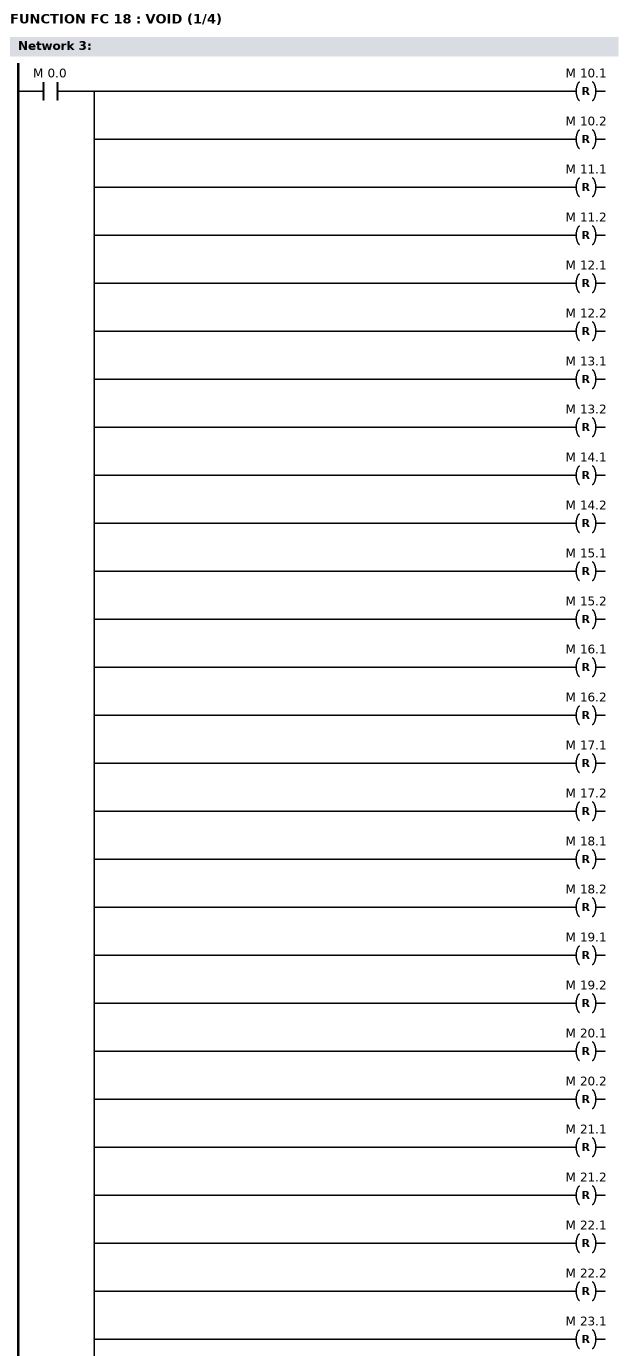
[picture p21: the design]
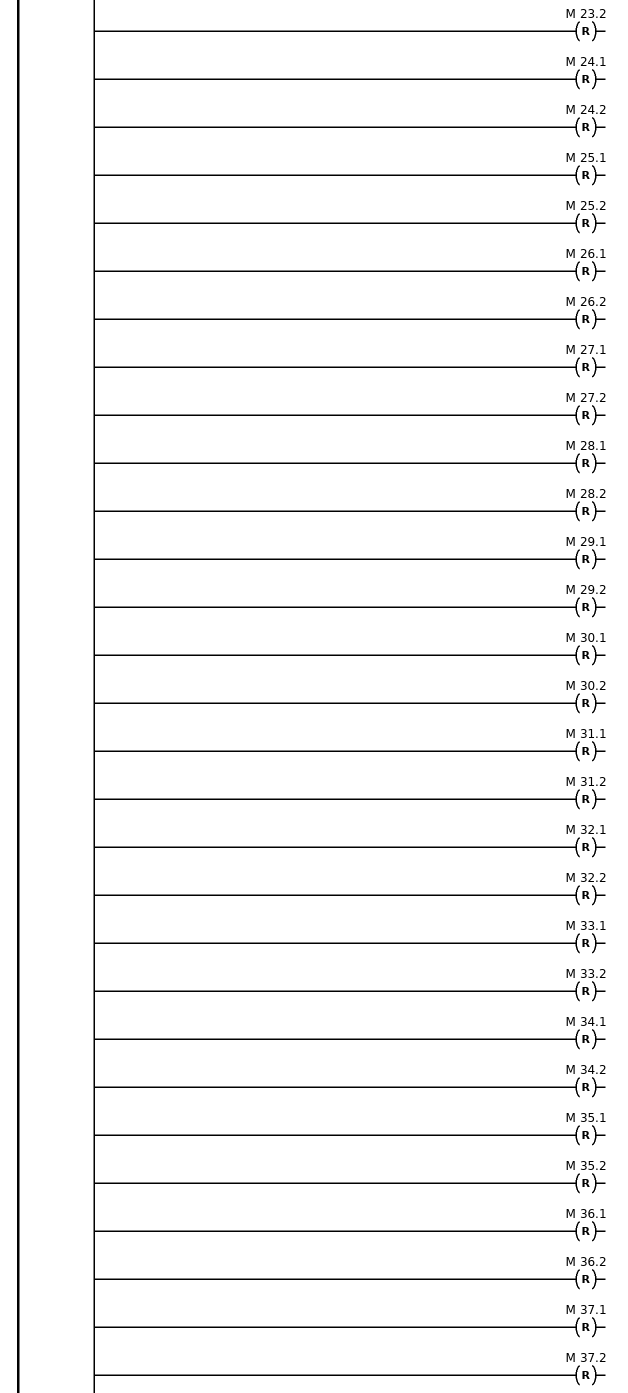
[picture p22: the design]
FUNCTION FC 33 : VOID
  NAME: INITREG  // INIT REG
  BEGIN
  NETWORK
       //;
       L   2#0000000000000001;
       T   MB 160;
       T   MB 161;
       T   MW 164;
       L   2#0000000000000000;
       T   MW 162;
       //;
       //;
       OPN DB 200;
  //      CALL OB 250;
  // *** Error in Line    5060  (FB 200):  Block does not exist. ***
       OPN DB 201;
  //      CALL OB 250;
  // *** Error in Line    5063  (FB 200):  Block does not exist. ***
       OPN DB 202;
  //      CALL OB 250;
  // *** Error in Line    5066  (FB 200):  Block does not exist. ***
       OPN DB 203;
  //      CALL OB 250;
  // *** Error in Line    5069  (FB 200):  Block does not exist. ***
       OPN DB 204;
  //      CALL OB 250;
  // *** Error in Line    5072  (FB 200):  Block does not exist. ***
       OPN DB 205;
  //      CALL OB 250;
  // *** Error in Line    5075  (FB 200):  Block does not exist. ***
       OPN DB 206;
  //      CALL OB 250;
  // *** Error in Line    5078  (FB 200):  Block does not exist. ***
       OPN DB 207;
  //      CALL OB 250;
  // *** Error in Line    5081  (FB 200):  Block does not exist. ***
       OPN DB 208;
  //      CALL OB 250;
  // *** Error in Line    5084  (FB 200):  Block does not exist. ***
       OPN DB 209;
  //      CALL OB 250;
  // *** Error in Line    5087  (FB 200):  Block does not exist. ***
       OPN DB 210;
  //      CALL OB 250;
  // *** Error in Line    5090  (FB 200):  Block does not exist. ***
       OPN DB 211;
  //      CALL OB 250;
  // *** Error in Line    5093  (FB 200):  Block does not exist. ***
       OPN DB 212;
  //      CALL OB 250;
  // *** Error in Line    5096  (FB 200):  Block does not exist. ***
       OPN DB 213;
  //      CALL OB 250;
  // *** Error in Line    5099  (FB 200):  Block does not exist. ***
       OPN DB 214;
  //      CALL OB 250;
  // *** Error in Line    5102  (FB 200):  Block does not exist. ***
       OPN DB 215;
  //      CALL OB 250;
  // *** Error in Line    5105  (FB 200):  Block does not exist. ***
       OPN DB 216;
  //      CALL OB 250;
  // *** Error in Line    5108  (FB 200):  Block does not exist. ***
       OPN DB 217;
  //      CALL OB 250;
  // *** Error in Line    5111  (FB 200):  Block does not exist. ***
       OPN DB 218;
  //      CALL OB 250;
  // *** Error in Line    5114  (FB 200):  Block does not exist. ***
       OPN DB 219;
  //      CALL OB 250;
  // *** Error in Line    5117  (FB 200):  Block does not exist. ***
       OPN DB 220;
  //      CALL OB 250;
  // *** Error in Line    5120  (FB 200):  Block does not exist. ***
       OPN DB 221;
  //      CALL OB 250;
  // *** Error in Line    5123  (FB 200):  Block does not exist. ***
       OPN DB 222;
  //      CALL OB 250;
  // *** Error in Line    5126  (FB 200):  Block does not exist. ***
       OPN DB 223;
  //      CALL OB 250;
  // *** Error in Line    5129  (FB 200):  Block does not exist. ***
       OPN DB 224;
  //      CALL OB 250;
  // *** Error in Line    5132  (FB 200):  Block does not exist. ***
       OPN DB 225;
  //      CALL OB 250;
  // *** Error in Line    5135  (FB 200):  Block does not exist. ***
       OPN DB 226;
  //      CALL OB 250;
  // *** Error in Line    5138  (FB 200):  Block does not exist. ***
       OPN DB 227;
  //      CALL OB 250;
  // *** Error in Line    5141  (FB 200):  Block does not exist. ***
       //;
END_FUNCTION

FUNCTION FC 15 : VOID
  NAME: MOTOR
  BEGIN
  NETWORK
  TITLE = MOTOR 05
  NETWORK
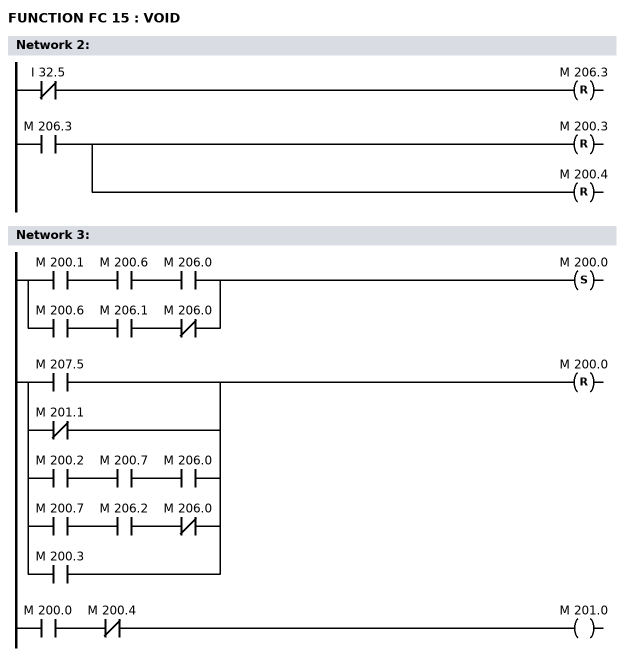
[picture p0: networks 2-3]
       AN  I 32.5;
       R   M 206.3;
       //;
       A   M 206.3;
       R   M 200.3;
       R   M 200.4;
  NETWORK
       A   M 200.1;
       A   M 200.6;
       A   M 206.0;
       O;
       A   M 200.6;
       A   M 206.1;
       AN  M 206.0;
       S   M 200.0;
       O   M 207.5;
       ON  M 201.1;
       O;
       A   M 200.2;
       A   M 200.7;
       A   M 206.0;
       O;
       A   M 200.7;
       A   M 206.2;
       AN  M 206.0;
       O   M 200.3;
       R   M 200.0;
       A   M 200.0;
       AN  M 200.4;
       =   M 201.0;
  NETWORK
  NETWORK
       AN  M 201.0;
       A   M 201.2;
       O;
       A   M 201.0;
       AN  M 201.2;
       =   M 209.0;
       AN  M 206.7;
       AN  M 209.0;
       =   M 209.1;
       AN  M 209.0;
       =   M 206.7;
       A   M 209.1;
       JC  M001;
       A   M 209.0;
       A   M 4.2;
       JC  M002;
       JU  M003;
  M001:L   15;
       T   MW 204;
       JU  M003;
  M002:L   MW 204;
       L   0;
       ==I;
       JC  M003;
       L   MW 204;
       +   -1;
       T   MW 204;
  M003:  NOP 0;
    NETWORK
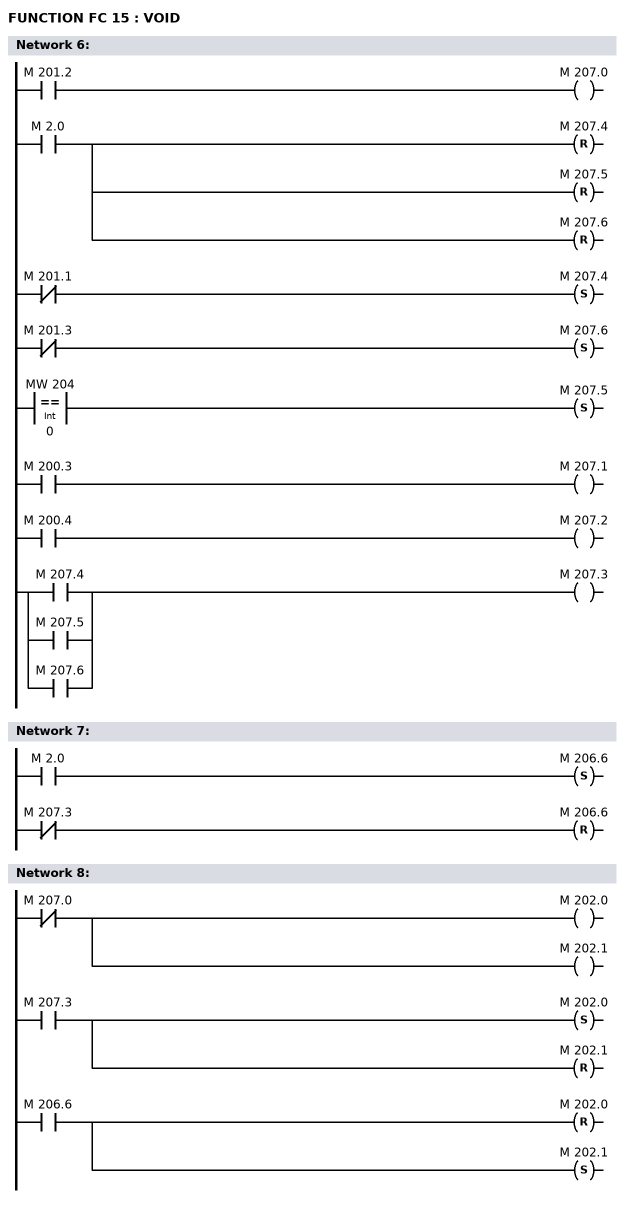
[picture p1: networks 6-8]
       A   M 201.2;
       =   M 207.0;
       A   M 2.0;
       R   M 207.4;
       R   M 207.5;
       R   M 207.6;
       AN  M 201.1;
       S   M 207.4;
       AN  M 201.3;
       S   M 207.6;
       L   MW 204;
       L   0;
       ==I;
       S   M 207.5;
       A   M 200.3;
       =   M 207.1;
       A   M 200.4;
       =   M 207.2;
       A   M 207.4;
       O   M 207.5;
       O   M 207.6;
       =   M 207.3;
  NETWORK
       A   M 2.0;
       S   M 206.6;
       AN  M 207.3;
       R   M 206.6;
  NETWORK
       AN  M 207.0;
       =   M 202.0;
       =   M 202.1;
       //;
       A   M 207.3;
       S   M 202.0;
       R   M 202.1;
       //;
       A   M 206.6;
       R   M 202.0;
       S   M 202.1;
       //;
  NETWORK
END_FUNCTION

FUNCTION FC 16 : VOID
  NAME: KLEP20  // KLEP 20
  BEGIN
  NETWORK
  NETWORK
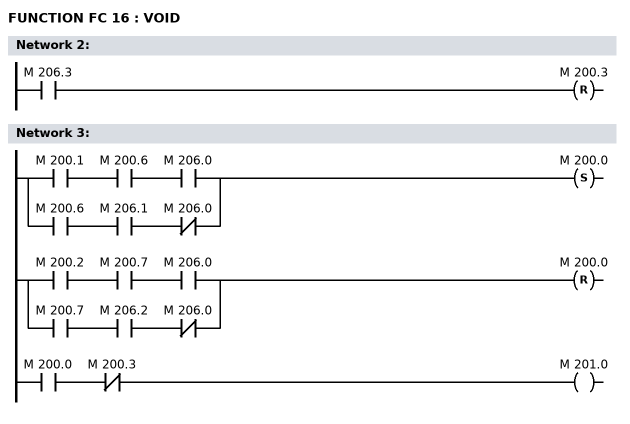
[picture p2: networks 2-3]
       A   M 206.3;
       R   M 200.3;
  NETWORK
       A   M 200.1;
       A   M 200.6;
       A   M 206.0;
       O;
       A   M 200.6;
       A   M 206.1;
       AN  M 206.0;
       S   M 200.0;
       A   M 200.2;
       A   M 200.7;
       A   M 206.0;
       O;
       A   M 200.7;
       A   M 206.2;
       AN  M 206.0;
       R   M 200.0;
       A   M 200.0;
       AN  M 200.3;
       =   M 201.0;
  NETWORK
  NETWORK
       AN  M 201.0;
       AN  M 201.2;
       O;
       A   M 201.0;
       AN  M 201.1;
       =   M 209.0;
       A   M 206.7;
       AN  M 209.0;
       =   M 209.1;
       A   M 209.0;
       =   M 206.7;
       A   M 209.1;
       JC  M001;
       A   M 209.0;
       A   M 4.2;
       JC  M002;
       JU  M003;
  M001:L   60;
       T   MW 204;
       JU  M003;
  M002:L   MW 204;
       L   0;
       ==I;
       JC  M003;
       L   MW 204;
       +   -1;
       T   MW 204;
  M003:  NOP 0;
    NETWORK
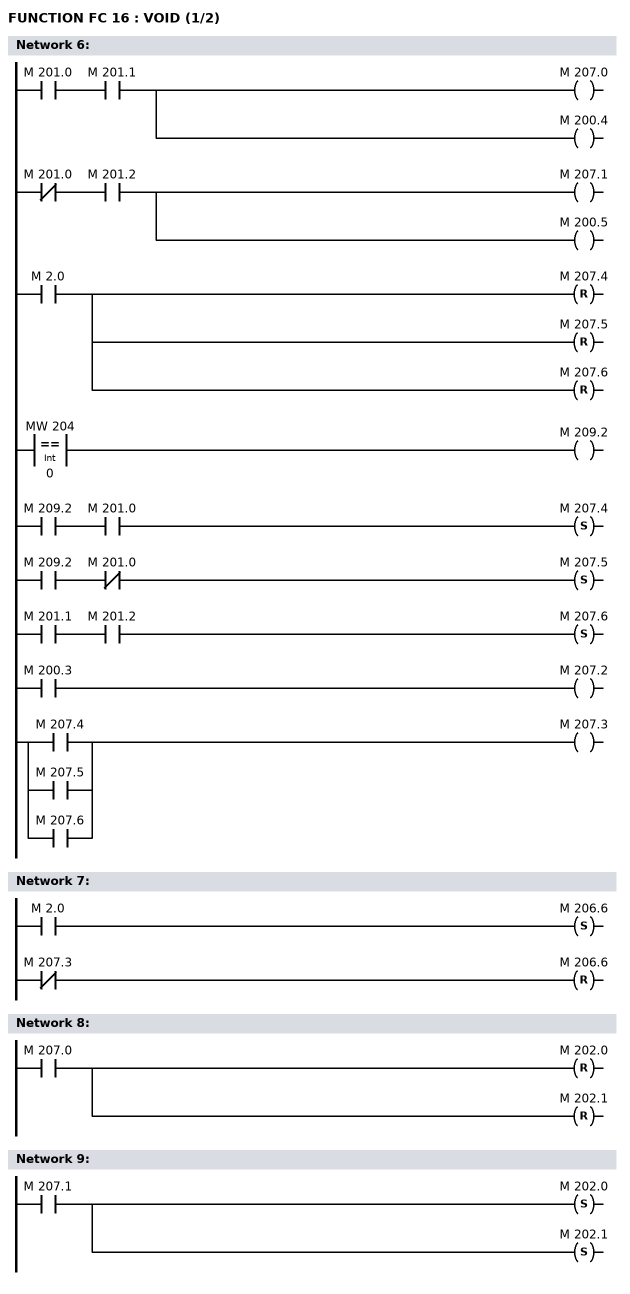
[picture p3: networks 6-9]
       A   M 201.0;
       A   M 201.1;
       =   M 207.0;
       =   M 200.4;
       AN  M 201.0;
       A   M 201.2;
       =   M 207.1;
       =   M 200.5;
       A   M 2.0;
       R   M 207.4;
       R   M 207.5;
       R   M 207.6;
       L   MW 204;
       L   0;
       ==I;
       =   M 209.2;
       A   M 209.2;
       A   M 201.0;
       S   M 207.4;
       A   M 209.2;
       AN  M 201.0;
       S   M 207.5;
       A   M 201.1;
       A   M 201.2;
       S   M 207.6;
       A   M 200.3;
       =   M 207.2;
       A   M 207.4;
       O   M 207.5;
       O   M 207.6;
       =   M 207.3;
  NETWORK
       A   M 2.0;
       S   M 206.6;
       AN  M 207.3;
       R   M 206.6;
  NETWORK
       A   M 207.0;
       R   M 202.0;
       R   M 202.1;
  NETWORK
       A   M 207.1;
       S   M 202.0;
       S   M 202.1;
  NETWORK
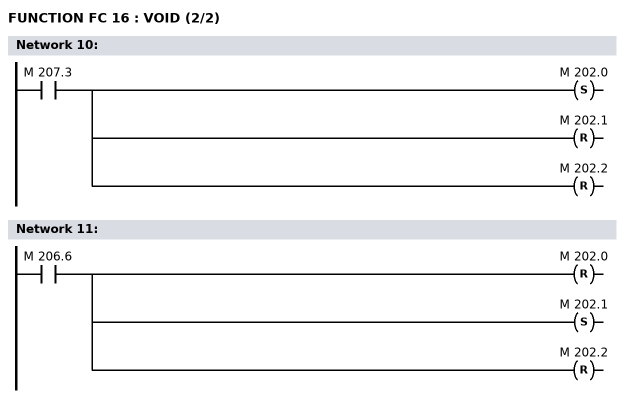
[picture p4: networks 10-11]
       A   M 207.3;
       S   M 202.0;
       R   M 202.1;
       R   M 202.2;
  NETWORK
       A   M 206.6;
       R   M 202.0;
       S   M 202.1;
       R   M 202.2;
  NETWORK


END_FUNCTION

FUNCTION FC 17 : VOID
  NAME: NVKLP20  // NVKLP 20
  BEGIN
  NETWORK
  NETWORK
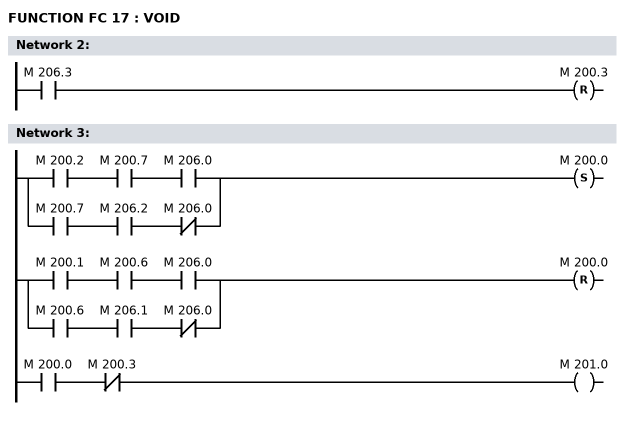
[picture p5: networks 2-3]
       A   M 206.3;
       R   M 200.3;
  NETWORK
       A   M 200.2;
       A   M 200.7;
       A   M 206.0;
       O;
       A   M 200.7;
       A   M 206.2;
       AN  M 206.0;
       S   M 200.0;
       A   M 200.1;
       A   M 200.6;
       A   M 206.0;
       O;
       A   M 200.6;
       A   M 206.1;
       AN  M 206.0;
       R   M 200.0;
       A   M 200.0;
       AN  M 200.3;
       =   M 201.0;
  NETWORK
  NETWORK
       A   M 201.0;
       AN  M 201.2;
       O;
       AN  M 201.0;
       AN  M 201.1;
       =   M 209.0;
       A   M 206.7;
       AN  M 209.0;
       =   M 209.1;
       A   M 209.0;
       =   M 206.7;
       A   M 209.1;
       JC  M001;
       A   M 209.0;
       A   M 4.2;
       JC  M002;
       JU  M003;
  M001:L   20;
       T   MW 204;
       JU  M003;
  M002:L   MW 204;
       L   0;
       ==I;
       JC  M003;
       L   MW 204;
       +   -1;
       T   MW 204;
  M003:  NOP 0;
    NETWORK
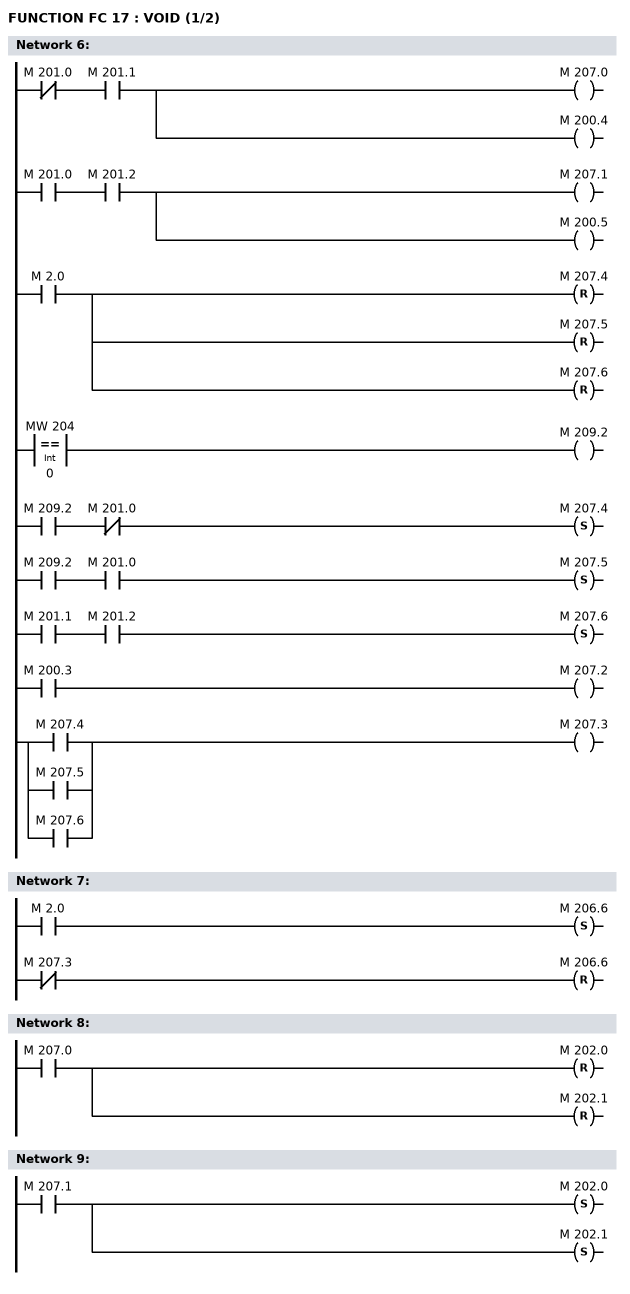
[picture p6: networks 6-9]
       AN  M 201.0;
       A   M 201.1;
       =   M 207.0;
       =   M 200.4;
       A   M 201.0;
       A   M 201.2;
       =   M 207.1;
       =   M 200.5;
       A   M 2.0;
       R   M 207.4;
       R   M 207.5;
       R   M 207.6;
       L   MW 204;
       L   0;
       ==I;
       =   M 209.2;
       A   M 209.2;
       AN  M 201.0;
       S   M 207.4;
       A   M 209.2;
       A   M 201.0;
       S   M 207.5;
       A   M 201.1;
       A   M 201.2;
       S   M 207.6;
       A   M 200.3;
       =   M 207.2;
       A   M 207.4;
       O   M 207.5;
       O   M 207.6;
       =   M 207.3;
  NETWORK
       A   M 2.0;
       S   M 206.6;
       AN  M 207.3;
       R   M 206.6;
  NETWORK
       A   M 207.0;
       R   M 202.0;
       R   M 202.1;
  NETWORK
       A   M 207.1;
       S   M 202.0;
       S   M 202.1;
  NETWORK
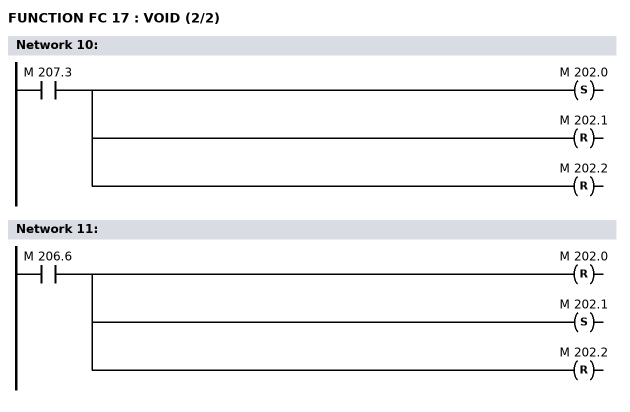
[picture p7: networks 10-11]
       A   M 207.3;
       S   M 202.0;
       R   M 202.1;
       R   M 202.2;
  NETWORK
       A   M 206.6;
       R   M 202.0;
       S   M 202.1;
       R   M 202.2;
  NETWORK


END_FUNCTION

FUNCTION FC 8 : VOID
  AUTHOR: _6107
  NAME: MK818STP
  BEGIN
  NETWORK
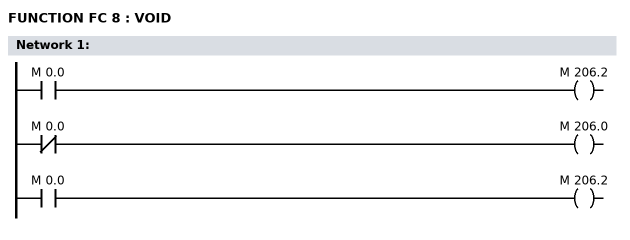
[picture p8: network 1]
       A   M 0.0;
       =   M 206.2;
       AN  M 0.0;
       =   M 206.0;
       A   M 0.0;
       =   M 206.2;


END_FUNCTION

FUNCTION FC 31 : VOID
  NAME: ANA_INKG  // ANA-INKG
  VAR_INPUT
    ANA       :word;      // ANA
    OPTI      :word;      // OPTI
    _DB       :block_db;  // DB
    VAN       :real;      // VAN
    TOT       :real;      // TOT
  END_VAR
  VAR_OUTPUT
    UITG      :dword;     // UITG
    UITF      :word;      // UITF
  END_VAR
  BEGIN
  NETWORK
       L   #ANA;
       L   8;
       /I;
       T   MW 200;
       //;
       L   #OPTI;
       T   MW 210;
       //;
       AN  M 211.0;
       JC  M001;
       L   MW 200;
       L   512;
       -I;
       T   MW 200;
       JU  M002;
       //;
  M001:AN  M 211.1;
       JC  M002;
       L   MW 200;
       L   39;
       +I;
       T   MW 200;
       //;
  M002:L   MW 200;
  //      CALL OB 220;
  // *** Error in Line    4796  (FB 150):  Block does not exist. ***
       DTR;
       T   MD 200;
       L   #TOT;
       L   #VAN;
       -R;
       L   +0.2048000E+04;
       /R;
       L   MD 200;
       *R;
       L   #VAN;
       +R;
       OPN #_DB ;
       T   #UITG;
       DTR;
       T   #UITF;


END_FUNCTION

FUNCTION FC 35 : VOID
  NAME: SCALE_UI  // SCALE-UI
  VAR_INPUT
    IN        :dword;     // IN
    VAN       :real;      // VAN
    TOT       :real;      // TOT
    DBIN      :block_db;  // DBIN
  END_VAR
  VAR_OUTPUT
    UIT       :word;      // UIT
  END_VAR
  BEGIN
  NETWORK
       OPN #DBIN ;
       L   #TOT;
       L   #VAN;
       -R;
       T   MD 200;
       L   #IN;
       L   #VAN;
       -R;
       L   MD 200;
       /R;
       L   +0.1024000E+04;
       *R;
       RND;
       T   MW 200;
       L   1024;
       >I;
       JC  M001;
       L   MW 200;
       L   -1024;
       <I;
       JC  M001;
       L   MW 200;
  M001:SLW 4;
       T   #UIT;


END_FUNCTION

FUNCTION FC 26 : VOID
  NAME: SEQ16
  BEGIN
  NETWORK
       //;
       //;
       //;
       AN  M 217.1;
       JC  M001;
       //;
       L   W#16#0;
       T   MW 210;
       L   W#16#1;
       T   MW 214;
       //;
       A   M 217.1;
       JC  M002;
       //;
  M001:A   M 211.1;
       AN  M 217.3;
       =   M 211.1;
       //;
       L   MW 210;
       L   W#16#0;
       OW;
       JZ  M003;
       //;
       L   W#16#FFFF;
       L   MW 212;
       XOW;
       L   MW 210;
       AW;
       JZ  M003;
       //;
       T   MW 214;
       T   MW 218;
       //;
       //;
  M002:A   M 0.1;
       =   M 217.1;
  M003:A   M 0.1;
       =   M 217.2;


END_FUNCTION

FUNCTION FC 27 : VOID
  NAME: SEQ32
  BEGIN
  NETWORK
       //;
       //;
       //;
       AN  M 101.2;
       JC  M001;
       //;
       L   W#16#0;
       SLW 15;
       T   MD 210;
       L   W#16#1;
       T   MD 218;
       //;
       A   M 101.2;
       JC  M002;
       //;
       //;
  M001:L   MW 210;
       L   W#16#0;
       OW;
       JP  M003;
       //;
       L   MW 212;
       L   W#16#0;
       OW;
       JZ  M004;
       //;
       //;
  M003:L   MD 210;
       T   MD 218;
       T   MD 226;
       L   W#16#0;
       SLW 15;
       T   MD 210;
       //;
  M002:A   M 0.1;
       =   M 101.2;
       //;
  M004:NOP 0;

END_FUNCTION

FUNCTION FC 28 : VOID
  NAME: ACTSTP
  BEGIN
  NETWORK
       //;
       //;
       A   M 0.1;
       =   M 223.0;
       //;
       L   MW 218;
       L   W#16#0;
       OW;
       JP  M001;
       //;
       L   MW 220;
       SSI 1;
       L   W#16#0;
       OW;
       JZ  M002;
       //;
  M001:A   M 0.0;
       =   M 223.0;
       //;
  M002:NOP 0;

END_FUNCTION

FUNCTION FC 29 : VOID
  NAME: GENTR
  BEGIN
  NETWORK
       L   MD 218;
       T   MD 230;
       //;
       L   W#16#1FF;
       L   MW 214;
       XOW;
       JP  M001;
       L   W#16#FFFE;
       L   MW 216;
       XOW;
       JZ  M002;
       //;
       //;
  M001:L   MD 230;
       //;
       A   M 233.0;
       A   M 109.2;
       JC  M003;
       //;
       A   M 233.0;
       JC  M004;
       //;
       A   M 230.0;
       JC  M004;
       //;
       A   M 109.2;
       A   M 231.7;
       JC  M003;
       //;
       SLD 1;
       AN  M 109.2;
       JC  M005;
       SLD 1;
       //;
       //;
  M005:T   MD 230;
       L   MW 216;
       AW;
       JP  M006;
       L   MW 230;
       L   MW 214;
       AW;
       JZ  M007;
       //;
  M006:L   MD 230;
       JU  M001;
       //;
       //;
  M003:L   W#16#0;
       T   MW 230;
       L   W#16#4;
       T   MW 232;
       JU  M005;
       //;
  M004:L   W#16#0;
       T   MW 230;
       L   W#16#2;
       T   MW 232;
       JU  M005;
       //;
  M007:L   MD 230;
       T   MD 210;
       A   M 0.0;
       =   M 223.3;
  M002:NOP 0;

END_FUNCTION

FUNCTION FC 30 : VOID
  NAME: KLPST
  BEGIN
  NETWORK
       AN  M 223.4;
       JC  M001;
       //;
       L   MW 218;
       L   W#16#1FF;
       AW;
       T   MW 230;
       //;
       L   MW 220;
       L   W#16#FFFE;
       AW;
       T   MW 232;
       JU  M002;
       //;
  M001:L   MW 218;
       L   W#16#0;
       AW;
       T   MW 230;
       //;
       L   MW 220;
       L   W#16#0;
       AW;
       T   MW 232;
       //;
  M002:NOP 0;

END_FUNCTION

FUNCTION FC 1 : VOID
  NAME: _FB3  // FB3
  BEGIN
  NETWORK
       //;
       OPN DB 94;
       A   I 25.1;
       L   DBW 82;
       SF  T 41;
       NOP 0;
       NOP 0;
       NOP 0;
       A   T 41;
       =   I 25.1;
       //;
       A   I 25.2;
       L   DBW 84;
       SF  T 42;
       NOP 0;
       NOP 0;
       NOP 0;
       A   T 42;
       =   I 25.2;
       //;
       A   I 25.3;
       L   DBW 86;
       SF  T 43;
       NOP 0;
       NOP 0;
       NOP 0;
       A   T 43;
       =   I 25.3;
       //;
       A   I 41.3;
       L   DBW 88;
       SF  T 44;
       NOP 0;
       NOP 0;
       NOP 0;
       A   T 44;
       =   I 41.3;
       //;
       A   I 25.6;
       L   DBW 126;
       SF  T 63;
       NOP 0;
       NOP 0;
       NOP 0;
       A   T 63;
       =   I 25.6;
       //;
       //;


END_FUNCTION

FUNCTION FC 2 : VOID
  NAME: STATISCH
  BEGIN
  NETWORK
       O   M 0.0;
       ON  M 0.0;
       //;
       S   M 0.0;
       //;
       R   M 0.5;
       //;
       S   Q 13.1;
  NETWORK


END_FUNCTION

FUNCTION FC 3 : VOID
  NAME: KETELTRP
  BEGIN
  NETWORK
  NETWORK
       L   0;
       T   MW 200;
       T   MW 202;
       T   MW 204;
       T   MW 206;
       //;
  NETWORK
       AN  M 2.2;
       JC  M001;
       //;
       OPN DB 120;
       //;
       L   0;
       T   DBB 220;
       T   DBB 221;
       T   DBB 222;
       T   DBB 223;
       T   DBB 224;
       T   DBB 225;
       T   DBB 226;
       T   DBB 227;
  M001:NOP 0;
  NETWORK
       OPN DB 94;
       L   DBW 196;
       A   I 47.5;
       SF  T 98;
       //;
  NETWORK
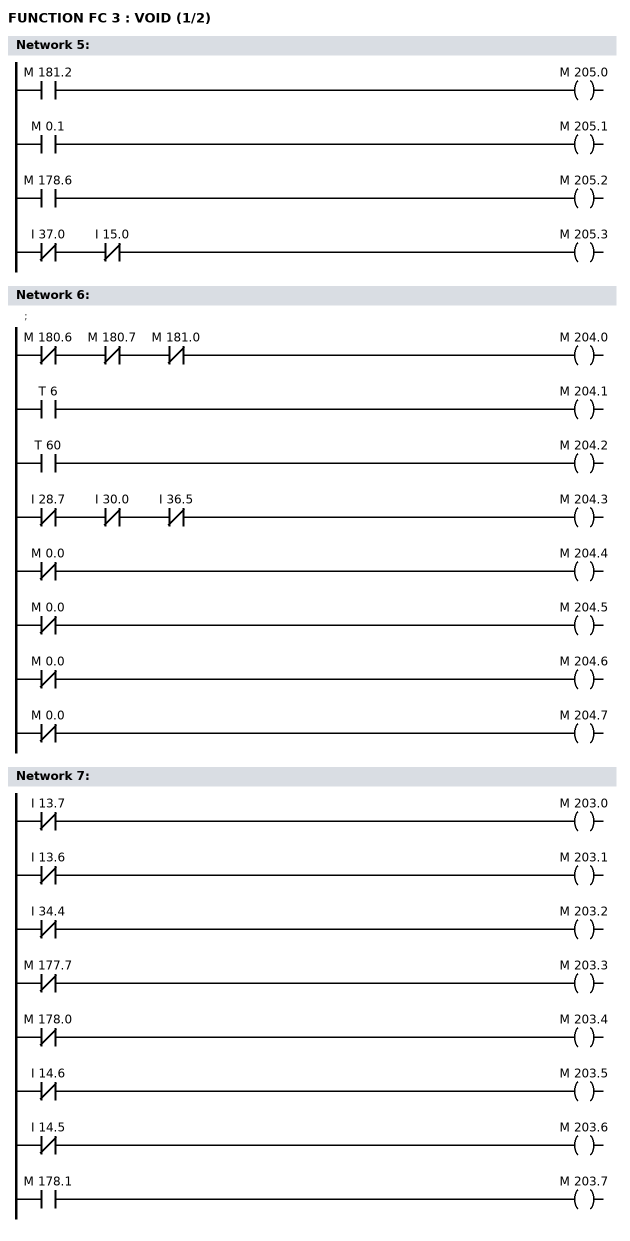
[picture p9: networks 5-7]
       A   M 181.2;
       =   M 205.0;
       A   M 0.1;
       =   M 205.1;
       A   M 178.6;
       =   M 205.2;
       AN  I 37.0;
       AN  I 15.0;
       =   M 205.3;
       //;
  NETWORK
       //;
       AN  M 180.6;
       AN  M 180.7;
       AN  M 181.0;
       =   M 204.0;
       A   T 6;
       =   M 204.1;
       A   T 60;
       =   M 204.2;
       AN  I 28.7;
       AN  I 30.0;
       AN  I 36.5;
       =   M 204.3;
       AN  M 0.0;
       =   M 204.4;
       AN  M 0.0;
       =   M 204.5;
       AN  M 0.0;
       =   M 204.6;
       AN  M 0.0;
       =   M 204.7;
  NETWORK
       AN  I 13.7;
       =   M 203.0;
       AN  I 13.6;
       =   M 203.1;
       AN  I 34.4;
       =   M 203.2;
       AN  M 177.7;
       =   M 203.3;
       AN  M 178.0;
       =   M 203.4;
       AN  I 14.6;
       =   M 203.5;
       AN  I 14.5;
       =   M 203.6;
       A   M 178.1;
       =   M 203.7;
       //;
  NETWORK
       //;
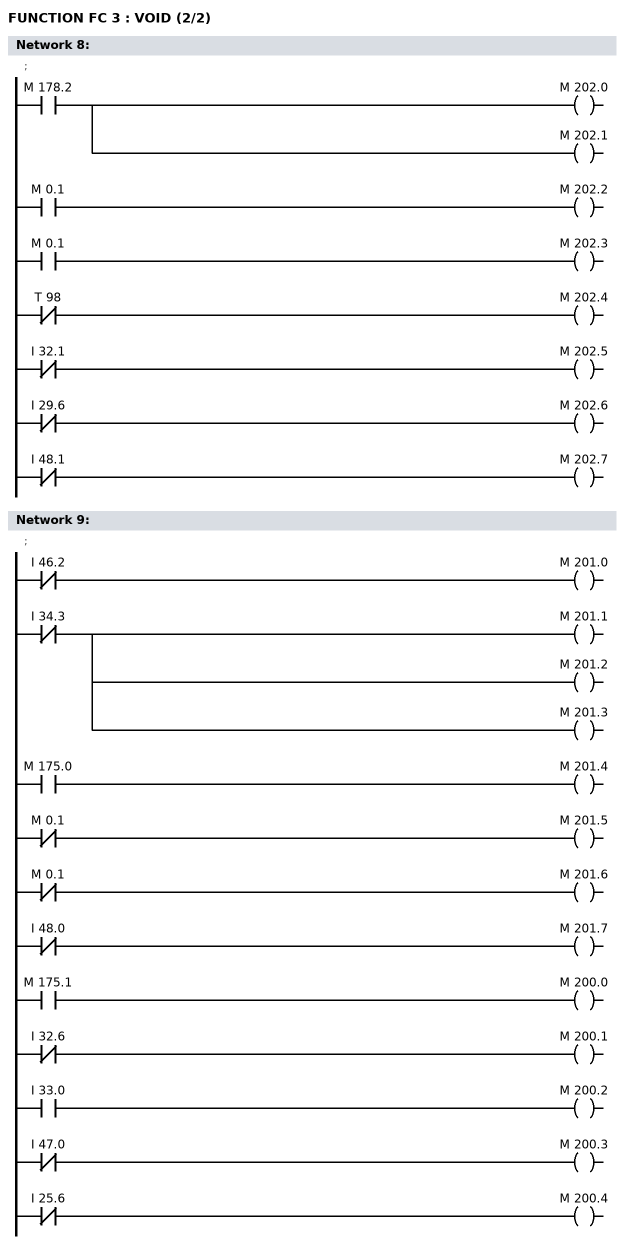
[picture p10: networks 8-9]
       A   M 178.2;
       =   M 202.0;
       //;
       =   M 202.1;
       A   M 0.1;
       =   M 202.2;
       A   M 0.1;
       =   M 202.3;
       AN  T 98;
       =   M 202.4;
       AN  I 32.1;
       =   M 202.5;
       AN  I 29.6;
       =   M 202.6;
       AN  I 48.1;
       =   M 202.7;
  NETWORK
       //;
       AN  I 46.2;
       =   M 201.0;
       AN  I 34.3;
       =   M 201.1;
       //;
       =   M 201.2;
       //;
       =   M 201.3;
       A   M 175.0;
       =   M 201.4;
       AN  M 0.1;
       =   M 201.5;
       AN  M 0.1;
       =   M 201.6;
       AN  I 48.0;
       =   M 201.7;
       A   M 175.1;
       =   M 200.0;
       AN  I 32.6;
       =   M 200.1;
       A   I 33.0;
       =   M 200.2;
       AN  I 47.0;
       =   M 200.3;
       AN  I 25.6;
       =   M 200.4;
       //;
  NETWORK
       OPN DB 120;
       //;
       A   M 0.0;
       R   DBX 219.0;
       //;
       L   MW 200;
       L   0;
       <>I;
       S   DBX 219.0;
       L   MW 202;
       L   0;
       <>I;
       S   DBX 219.0;
       L   MW 204;
       L   0;
       <>I;
       S   DBX 219.0;
       L   MW 206;
       L   0;
       <>I;
       S   DBX 219.0;
  NETWORK
       A   M 2.2;
       R   DBX 219.2;
       //;
       A   M 2.2;
       JC  M002;
       //;
       //;
       AN  M 109.5;
       JC  M003;
       //;
       L   MB 200;
       L   DBB 220;
       XOW;
       L   MB 200;
       AW;
       L   0;
       <>I;
       S   DBX 219.2;
       //;
       L   MB 201;
       L   DBB 221;
       XOW;
       L   MB 201;
       AW;
       L   0;
       <>I;
       S   DBX 219.2;
       //;
       L   MB 202;
       L   DBB 222;
       XOW;
       L   MB 202;
       AW;
       L   0;
       <>I;
       S   DBX 219.2;
       //;
       L   MB 203;
       L   DBB 223;
       XOW;
       L   MB 203;
       AW;
       L   0;
       <>I;
       S   DBX 219.2;
       //;
       L   MB 204;
       L   DBB 224;
       XOW;
       L   MB 204;
       AW;
       L   0;
       <>I;
       S   DBX 219.2;
       //;
       L   MB 205;
       L   DBB 225;
       XOW;
       L   MB 205;
       AW;
       L   0;
       <>I;
       S   DBX 219.2;
       //;
       L   MB 206;
       L   DBB 226;
       XOW;
       L   MB 206;
       AW;
       L   0;
       <>I;
       S   DBX 219.2;
       //;
       L   MB 207;
       L   DBB 227;
       XOW;
       L   MB 207;
       AW;
       L   0;
       <>I;
       S   DBX 219.2;
  M003:NOP 0;
       //;
       A   M 109.5;
       AN  DBX 219.1;
       A   DBX 219.2;
       JC  M004;
       //;
       AN  M 109.5;
       A   DBX 219.0;
       JC  M002;
       //;
       AN  DBX 219.0;
       A   DBX 219.1;
       JC  M005;
       JU  M006;
       //;
  M002:L   MB 200;
       L   DBB 220;
       OW;
       T   DBB 220;
       //;
       L   MB 201;
       L   DBB 221;
       OW;
       T   DBB 221;
       //;
       L   MB 202;
       L   DBB 222;
       OW;
       T   DBB 222;
       //;
       L   MB 203;
       L   DBB 223;
       OW;
       T   DBB 223;
       //;
       L   MB 204;
       L   DBB 224;
       OW;
       T   DBB 224;
       //;
       L   MB 205;
       L   DBB 225;
       OW;
       T   DBB 225;
       //;
       L   MB 206;
       L   DBB 226;
       OW;
       T   DBB 226;
       //;
       L   MB 207;
       L   DBB 227;
       OW;
       T   DBB 227;
       //;
       JU  M006;
       //;
  M004:NOP 0;
       L   MD 200;
       T   DBD 220;
       //;
       L   MD 204;
       T   DBD 224;
       //;
       JU  M006;
       //;
  M005:NOP 0;
       L   DBD 296;
       T   DBD 304;
       L   DBD 292;
       T   DBD 300;
       //;
       L   DBD 288;
       T   DBD 296;
       L   DBD 284;
       T   DBD 292;
       //;
       L   DBD 280;
       T   DBD 288;
       L   DBD 276;
       T   DBD 284;
       //;
       L   DBD 272;
       T   DBD 280;
       L   DBD 268;
       T   DBD 276;
       //;
       L   DBD 264;
       T   DBD 272;
       L   DBD 260;
       T   DBD 268;
       //;
       L   DBD 256;
       T   DBD 264;
       L   DBD 252;
       T   DBD 260;
       //;
       //;
       L   DBD 248;
       T   DBD 256;
       L   DBD 244;
       T   DBD 252;
       //;
       L   DBD 240;
       T   DBD 248;
       L   DBD 236;
       T   DBD 244;
       //;
       L   DBD 232;
       T   DBD 240;
       L   DBD 228;
       T   DBD 236;
       //;
       L   DBD 224;
       T   DBD 232;
       L   DBD 220;
       T   DBD 228;
       //;
       L   W#16#0;
       T   DBW 226;
       T   DBW 224;
       T   DBW 222;
       T   DBW 220;
       //;
  M006:A   DBX 219.2;
       =   DBX 219.1;
  NETWORK


END_FUNCTION

FUNCTION FC 4 : VOID
  NAME: GWS_SEN  // GWS-SEN
  BEGIN
  NETWORK
  NETWORK
       OPN DB 133;
       L   DBW 56;
       L   1662;
       >I;
       S   M 176.0;
       L   DBW 56;
       L   1658;
       <I;
       R   M 176.0;
  NETWORK
       OPN DB 133;
       L   DBW 56;
       L   1081;
       >I;
       S   M 176.1;
       L   DBW 56;
       L   1077;
       <I;
       R   M 176.1;
  NETWORK
       OPN DB 133;
       L   DBW 56;
       L   915;
       >I;
       S   M 176.2;
       L   DBW 56;
       L   911;
       <I;
       R   M 176.2;
  NETWORK
       OPN DB 130;
       L   DBW 188;
       L   698;
       >I;
       S   M 176.3;
       L   DBW 188;
       L   694;
       <I;
       R   M 176.3;
  NETWORK
       OPN DB 133;
       L   DBW 58;
       L   1662;
       >I;
       S   M 176.4;
       L   DBW 58;
       L   1658;
       <I;
       R   M 176.4;
  NETWORK
       OPN DB 133;
       L   DBW 58;
       L   1081;
       >I;
       S   M 176.5;
       L   DBW 58;
       L   1077;
       <I;
       R   M 176.5;
  NETWORK
       OPN DB 133;
       L   DBW 58;
       L   915;
       >I;
       S   M 176.6;
       L   DBW 58;
       L   911;
       <I;
       R   M 176.6;
  NETWORK
       OPN DB 130;
       L   DBW 190;
       L   698;
       >I;
       S   M 176.7;
       L   DBW 190;
       L   694;
       <I;
       R   M 176.7;
  NETWORK
       OPN DB 133;
       L   DBW 36;
       L   207;
       >I;
       S   M 177.0;
       L   DBW 36;
       L   203;
       <I;
       R   M 177.0;
  NETWORK
       OPN DB 133;
       L   DBW 38;
       L   207;
       >I;
       S   M 177.1;
       L   DBW 38;
       L   203;
       <I;
       R   M 177.1;
  NETWORK
       OPN DB 133;
       L   DBW 40;
       L   207;
       >I;
       S   M 177.2;
       L   DBW 40;
       L   203;
       <I;
       R   M 177.2;
  NETWORK
       OPN DB 130;
       L   DBW 318;
       L   417;
       >I;
       S   M 177.3;
       L   DBW 318;
       L   413;
       <I;
       R   M 177.3;
  NETWORK
       OPN DB 151;
       L   DBD 160;
       L   +0.4900000E+02;
       >R;
       S   M 177.5;
       L   DBD 160;
       L   +0.1000000E+02;
       <R;
       R   M 177.5;
  NETWORK
       OPN DB 130;
       L   DBW 26;
       L   207;
       >I;
       S   M 177.6;
       L   DBW 26;
       L   203;
       <I;
       R   M 177.6;
  NETWORK
       OPN DB 133;
       L   DBW 26;
       L   650;
       >I;
       S   M 177.7;
       L   DBW 26;
       L   585;
       <I;
       R   M 177.7;
  NETWORK
       OPN DB 133;
       L   DBW 28;
       L   623;
       >I;
       S   M 178.0;
       L   DBW 28;
       L   530;
       <I;
       R   M 178.0;
  NETWORK
       OPN DB 150;
       L   DBD 116;
       L   +0.1000000E+02;
       >R;
       R   M 178.1;
       L   DBD 116;
       L   +0.8000000E+01;
       <R;
       S   M 178.1;
       //;
       AN  M 178.1;
       =   Q 18.1;
  NETWORK
       L   DBD 116;
       L   +0.1500000E+03;
       >R;
       S   M 178.2;
       L   DBD 116;
       L   +0.1450000E+03;
       <R;
       R   M 178.2;
  NETWORK
       OPN DB 130;
       L   DBW 330;
       L   251;
       >I;
       S   M 178.4;
       L   DBW 82;
       L   247;
       <I;
       R   M 178.4;
  NETWORK
       OPN DB 130;
       L   DBW 108;
       L   1334;
       >I;
       S   M 178.3;
       L   DBW 108;
       L   1328;
       <I;
       R   M 178.3;
  NETWORK
       OPN DB 130;
       L   DBW 68;
       L   515;
       >I;
       R   Q 13.2;
       L   DBW 68;
       L   509;
       <I;
       S   Q 13.2;
  NETWORK
       OPN DB 130;
       L   DBW 68;
       L   105;
       >I;
       R   Q 13.3;
       L   DBW 68;
       L   99;
       <I;
       S   Q 13.3;
  NETWORK
       OPN DB 181;
       L   DBD 250;
       L   +0.1050000E+02;
       <R;
       S   M 158.0;
       L   DBD 250;
       L   +0.1080000E+02;
       >R;
       R   M 158.0;
       //;


END_FUNCTION

FUNCTION FC 5 : VOID
  NAME: GWS_SEN  // GWS-SEN
  BEGIN
  NETWORK
       OPN DB 130;
       L   DBW 262;
       L   959;
       >I;
       S   M 179.0;
       L   DBW 262;
       L   953;
       <I;
       R   M 179.0;
  NETWORK
       OPN DB 150;
       L   DBD 132;
       OPN DB 181;
       L   DBD 218;
       >R;
       S   M 178.5;
       //;
       OPN DB 150;
       L   DBD 132;
       OPN DB 181;
       L   DBD 222;
       <R;
       R   M 178.5;
  NETWORK
       OPN DB 130;
       L   DBW 26;
       L   1024;
       >I;
       S   M 179.1;
       L   DBW 26;
       L   922;
       <I;
       R   M 179.1;
  NETWORK
       OPN DB 130;
       L   DBW 82;
       L   717;
       >I;
       S   M 179.2;
       L   DBW 82;
       L   256;
       <I;
       R   M 179.2;
  NETWORK
       OPN DB 130;
       L   DBW 186;
       L   490;
       <I;
       S   M 179.3;
       //;
       L   DBW 186;
       L   533;
       >I;
       R   M 179.3;
  NETWORK
       OPN DB 130;
       L   DBW 178;
       L   490;
       <I;
       S   M 179.4;
       //;
       L   DBW 178;
       L   533;
       >I;
       R   M 179.4;
  NETWORK
       OPN DB 94;
       L   DBW 216;
       AN  I 35.7;
       SD  T 108;
       A   T 108;
       =   M 179.5;
  NETWORK
       OPN DB 151;
       L   DBD 104;
       L   +0.8000000E+02;
       >R;
       S   M 178.6;
       //;
       L   DBD 104;
       L   +0.7900000E+02;
       <R;
       R   M 178.6;
  NETWORK
       L   DBD 104;
       L   +0.7000000E+02;
       >R;
       S   M 179.6;
       //;
       L   DBD 104;
       L   +0.6900000E+02;
       <R;
       R   M 179.6;
  NETWORK
       OPN DB 150;
       L   DBD 244;
       L   +0.5052600E+02;
       >R;
       S   M 179.7;
       //;
       L   DBD 244;
       L   +0.4996500E+02;
       <R;
       R   M 179.7;
  NETWORK
       L   DBD 244;
       L   +0.2080800E+03;
       >R;
       S   M 180.0;
       //;
       L   DBD 244;
       L   +0.2054700E+03;
       <R;
       R   M 180.0;
  NETWORK
       OPN DB 150;
       L   DBD 240;
       L   +0.5000000E+01;
       >R;
       S   M 180.1;
       //;
       L   DBD 240;
       L   +0.4000000E+01;
       <R;
       R   M 180.1;
  NETWORK
       OPN DB 130;
       L   DBW 152;
       +   512;
       L   410;
       >I;
       S   M 180.2;
       //;
       L   DBW 152;
       +   512;
       L   421;
       <I;
       R   M 180.2;
  NETWORK
       OPN DB 152;
       L   DBD 116;
       L   +0.2350000E+03;
       >R;
       S   M 180.3;
       //;
       L   DBD 116;
       L   +0.2300000E+03;
       <R;
       R   M 180.3;
  NETWORK
       OPN DB 151;
       L   DBD 36;
       L   +0.4000000E+02;
       >R;
       S   M 180.4;
       //;
       L   DBD 36;
       L   +0.4100000E+02;
       <R;
       R   M 180.4;
       //;
  NETWORK
       OPN DB 130;
       L   DBW 152;
       +   512;
       L   1843;
       >I;
       S   M 180.5;
       //;
       L   DBW 152;
       L   1823;
       <I;
       R   M 180.5;
  NETWORK
       OPN DB 150;
       L   DBD 60;
       L   +0.2000000E+03;
       >R;
       S   M 180.6;
       //;
       L   DBD 60;
       L   +0.2080000E+03;
       <R;
       R   M 180.6;
  NETWORK
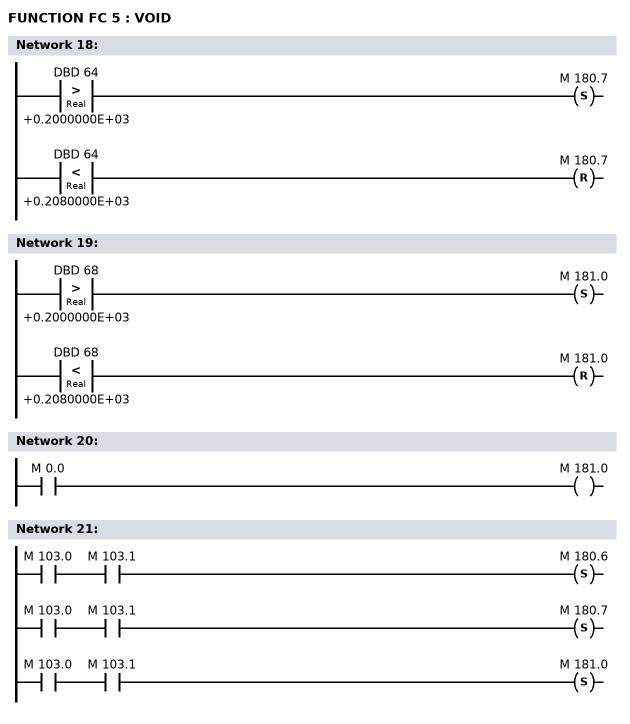
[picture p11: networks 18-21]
       L   DBD 64;
       L   +0.2000000E+03;
       >R;
       S   M 180.7;
       //;
       L   DBD 64;
       L   +0.2080000E+03;
       <R;
       R   M 180.7;
  NETWORK
       L   DBD 68;
       L   +0.2000000E+03;
       >R;
       S   M 181.0;
       //;
       L   DBD 68;
       L   +0.2080000E+03;
       <R;
       R   M 181.0;
  NETWORK
       A   M 0.0;
       =   M 181.0;
  NETWORK
       A   M 103.0;
       A   M 103.1;
       S   M 180.6;
       A   M 103.0;
       A   M 103.1;
       S   M 180.7;
       A   M 103.0;
       A   M 103.1;
       S   M 181.0;
  NETWORK
       OPN DB 151;
       L   DBD 116;
       L   +0.2200000E+03;
       >R;
       S   M 181.1;
       //;
       L   DBD 116;
       L   +0.2180000E+03;
       <R;
       R   M 181.1;
  NETWORK
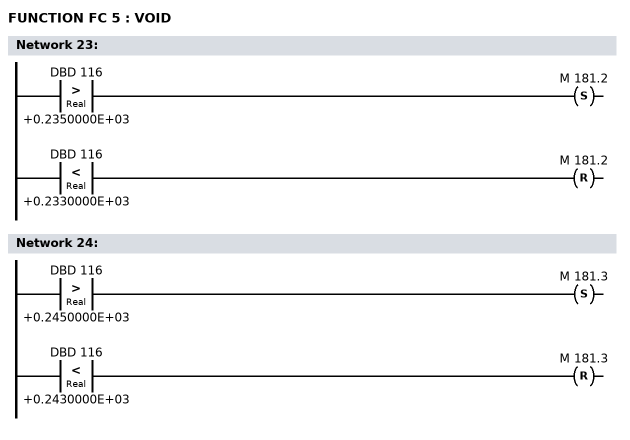
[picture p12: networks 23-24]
       L   DBD 116;
       L   +0.2350000E+03;
       >R;
       S   M 181.2;
       //;
       L   DBD 116;
       L   +0.2330000E+03;
       <R;
       R   M 181.2;
  NETWORK
       L   DBD 116;
       L   +0.2450000E+03;
       >R;
       S   M 181.3;
       //;
       L   DBD 116;
       L   +0.2430000E+03;
       <R;
       R   M 181.3;
       //;


END_FUNCTION

FUNCTION FC 6 : VOID
  NAME: GWS_SEN  // GWS-SEN
  BEGIN
  NETWORK
       OPN DB 130;
  NETWORK
       L   DBW 156;
       L   410;
       >I;
       S   M 181.4;
       //;
       L   DBW 156;
       L   431;
       <I;
       R   M 181.4;
  NETWORK
       OPN DB 150;
       L   DBD 172;
       L   +0.2500000E+02;
       >R;
       S   M 181.5;
       //;
       L   DBD 172;
       L   +0.2200000E+02;
       <R;
       R   M 181.5;
  NETWORK
       L   DBD 12;
       L   +0.5000000E+02;
       >R;
       S   M 181.6;
       //;
       L   DBD 12;
       L   +0.4500000E+02;
       <R;
       R   M 181.6;
  NETWORK
       OPN DB 130;
       L   DBW 132;
       L   410;
       >I;
       S   M 174.0;
       //;
       L   DBW 132;
       L   431;
       <I;
       R   M 174.0;
  NETWORK
       L   DBW 134;
       L   307;
       >I;
       S   M 174.1;
       //;
       L   DBW 134;
       L   337;
       <I;
       R   M 174.1;
  NETWORK
       OPN DB 150;
       L   DBD 28;
       L   DBD 92;
       -R;
       L   +0.4150000E+00;
       >R;
       S   M 174.2;
       //;
       L   DBD 28;
       L   DBD 92;
       -R;
       L   +0.3800000E+00;
       <R;
       R   M 174.2;
       //;
       A   M 174.2;
       JC  M001;
       //;
       L   DBD 28;
       L   DBD 92;
       -R;
       L   -0.4150000E+00;
       <R;
       S   M 174.2;
       //;
       L   DBD 28;
       L   DBD 92;
       -R;
       L   -0.3799999E+00;
       >R;
       R   M 174.2;
       //;
  M001:  NOP 0;
    NETWORK
       L   DBD 144;
       L   DBD 248;
       -R;
       L   +0.4150000E+00;
       >R;
       S   M 174.3;
       //;
       L   DBD 144;
       L   DBD 248;
       -R;
       L   +0.3800000E+00;
       <R;
       R   M 174.3;
       //;
       A   M 174.3;
       JC  M002;
       //;
       L   DBD 144;
       L   DBD 248;
       -R;
       L   -0.4150000E+00;
       <R;
       S   M 174.3;
       //;
       L   DBD 144;
       L   DBD 248;
       -R;
       L   -0.3799999E+00;
       >R;
       R   M 174.3;
       //;
  M002:  NOP 0;
    NETWORK
       L   DBD 136;
       L   DBD 252;
       -R;
       L   +0.4150000E+00;
       >R;
       S   M 174.4;
       //;
       L   DBD 136;
       L   DBD 252;
       -R;
       L   +0.3800000E+00;
       <R;
       R   M 174.4;
       //;
       A   M 174.4;
       JC  M003;
       //;
       L   DBD 136;
       L   DBD 252;
       -R;
       L   -0.4150000E+00;
       <R;
       S   M 174.4;
       //;
       L   DBD 136;
       L   DBD 252;
       -R;
       L   -0.3799999E+00;
       >R;
       R   M 174.4;
       //;
  M003:  NOP 0;
    NETWORK
       L   DBD 140;
       L   DBD 192;
       -R;
       L   +0.4150000E+00;
       >R;
       S   M 174.5;
       //;
       L   DBD 140;
       L   DBD 192;
       -R;
       L   +0.3800000E+00;
       <R;
       R   M 174.5;
       //;
       A   M 174.5;
       JC  M004;
       //;
       L   DBD 140;
       L   DBD 192;
       -R;
       L   -0.4150000E+00;
       <R;
       S   M 174.5;
       //;
       L   DBD 140;
       L   DBD 192;
       -R;
       L   -0.3799999E+00;
       >R;
       R   M 174.5;
       //;
  M004:  NOP 0;
    NETWORK
       L   DBD 196;
       L   DBD 200;
       -R;
       L   +0.4150000E+00;
       >R;
       S   M 174.6;
       //;
       L   DBD 196;
       L   DBD 200;
       -R;
       L   +0.3800000E+00;
       <R;
       R   M 174.6;
       //;
       A   M 174.6;
       JC  M005;
       //;
       L   DBD 196;
       L   DBD 200;
       -R;
       L   -0.4150000E+00;
       <R;
       S   M 174.6;
       //;
       L   DBD 196;
       L   DBD 200;
       -R;
       L   -0.3799999E+00;
       >R;
       R   M 174.6;
  M005:  NOP 0;
    NETWORK
       OPN DB 152;
       L   DBD 60;
       L   +0.6000000E+03;
       >R;
       S   M 181.7;
       //;
       L   DBD 60;
       L   +0.5950000E+03;
       <R;
       R   M 181.7;
  NETWORK
       OPN DB 152;
       L   DBD 112;
       L   +0.1000000E+04;
       >R;
       S   M 174.7;
       //;
       L   DBD 112;
       L   +0.9950000E+03;
       <R;
       R   M 174.7;
  NETWORK
       OPN DB 180;
       L   DBD 66;
       L   +0.9999999E-01;
       >R;
       S   M 177.4;
       //;
       L   DBD 66;
       L   +0.5555555E-01;
       <R;
       R   M 177.4;
       //;
  NETWORK
       OPN DB 152;
       L   DBD 72;
       L   +0.1000000E+04;
       >R;
       S   M 175.0;
       L   DBD 72;
       L   +0.9950000E+03;
       <R;
       R   M 175.0;
       //;
       AN  M 175.0;
       =   Q 17.7;
  NETWORK
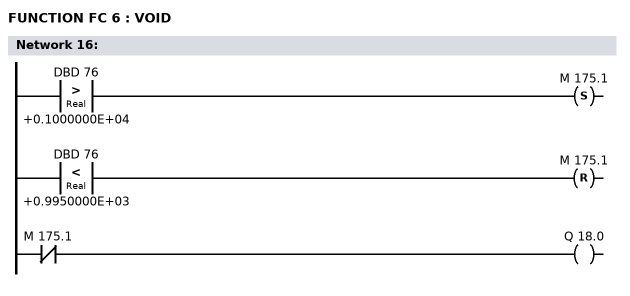
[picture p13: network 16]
       L   DBD 76;
       L   +0.1000000E+04;
       >R;
       S   M 175.1;
       L   DBD 76;
       L   +0.9950000E+03;
       <R;
       R   M 175.1;
       //;
       AN  M 175.1;
       =   Q 18.0;
  NETWORK
       OPN DB 152;
       L   DBD 48;
       L   +0.8000000E+03;
       <R;
       S   M 175.2;
       L   DBD 48;
       L   +0.8500000E+03;
       >R;
       R   M 175.2;
  NETWORK
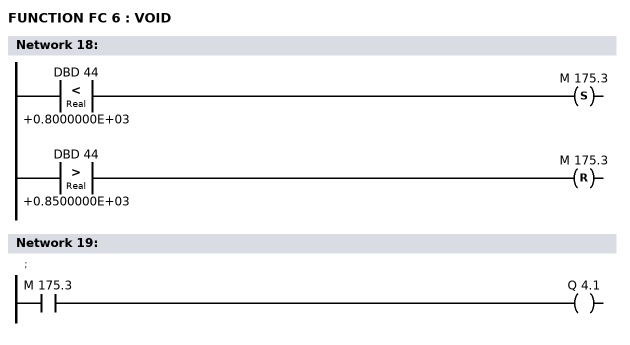
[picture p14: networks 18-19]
       L   DBD 44;
       L   +0.8000000E+03;
       <R;
       S   M 175.3;
       L   DBD 44;
       L   +0.8500000E+03;
       >R;
       R   M 175.3;
  NETWORK
       //;
       A   M 175.3;
       =   Q 4.1;
  NETWORK
       OPN DB 152;
       L   DBD 44;
       L   +0.5500000E+03;
       <R;
       R   M 175.4;
       L   DBD 44;
       L   +0.6000000E+03;
       >R;
       S   M 175.4;
       //;
       OPN DB 182;
       L   DBD 2;
       L   +0.5000000E+02;
       -R;
       T   DBD 6;
       OPN DB 152;
       L   DBD 44;
       OPN DB 182;
       L   DBD 6;
       <R;
       R   M 173.7;
       OPN DB 152;
       L   DBD 44;
       OPN DB 182;
       L   DBD 2;
       >R;
       S   M 173.7;
       OPN DB 152;
       //;
  NETWORK
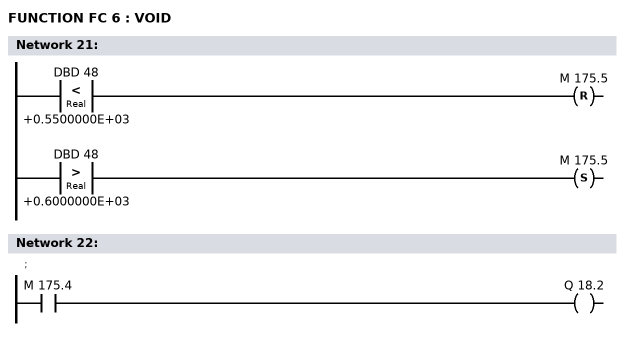
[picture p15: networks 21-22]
       L   DBD 48;
       L   +0.5500000E+03;
       <R;
       R   M 175.5;
       L   DBD 48;
       L   +0.6000000E+03;
       >R;
       S   M 175.5;
  NETWORK
       //;
       A   M 175.4;
       =   Q 18.2;
  NETWORK
       OPN DB 152;
       L   DBD 60;
       L   +0.9450000E+03;
       <R;
       R   M 175.6;
       L   DBD 60;
       L   +0.9500000E+03;
       >R;
       S   M 175.6;
  NETWORK
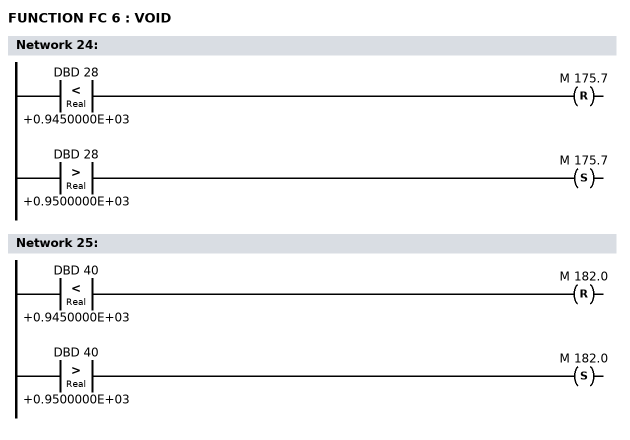
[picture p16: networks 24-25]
       L   DBD 28;
       L   +0.9450000E+03;
       <R;
       R   M 175.7;
       L   DBD 28;
       L   +0.9500000E+03;
       >R;
       S   M 175.7;
  NETWORK
       L   DBD 40;
       L   +0.9450000E+03;
       <R;
       R   M 182.0;
       L   DBD 40;
       L   +0.9500000E+03;
       >R;
       S   M 182.0;
  NETWORK
       OPN DB 151;
       L   DBD 164;
       L   +0.1900000E+03;
       >R;
       S   M 182.1;
       L   DBD 164;
       L   +0.1880000E+03;
       <R;
       R   M 182.1;
  NETWORK
       OPN DB 180;
       //;
       L   DBD 302;
       L   +0.5200000E+01;
       <R;
       S   M 182.3;
       //;
       L   DBD 302;
       L   +0.5200000E+01;
       >R;
       R   M 182.3;
       //;
       L   DBD 302;
       L   +0.6900000E+01;
       >R;
       S   M 182.2;
       //;
       L   DBD 302;
       L   +0.6900000E+01;
       <R;
       R   M 182.2;
  NETWORK
       //;
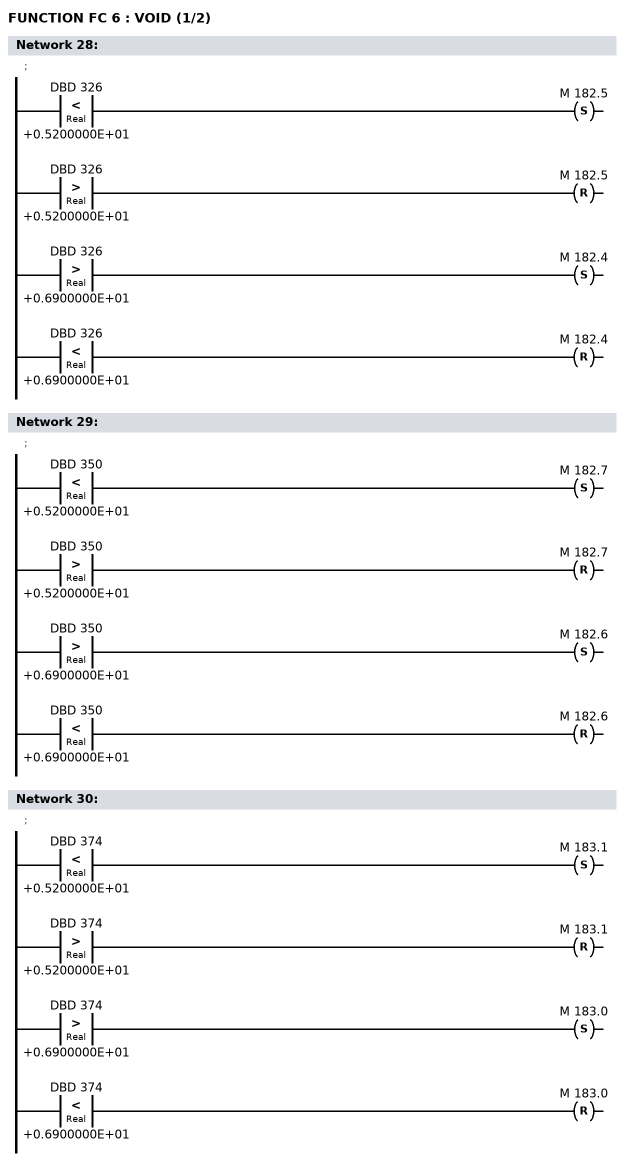
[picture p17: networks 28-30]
       L   DBD 326;
       L   +0.5200000E+01;
       <R;
       S   M 182.5;
       //;
       L   DBD 326;
       L   +0.5200000E+01;
       >R;
       R   M 182.5;
       //;
       L   DBD 326;
       L   +0.6900000E+01;
       >R;
       S   M 182.4;
       //;
       L   DBD 326;
       L   +0.6900000E+01;
       <R;
       R   M 182.4;
  NETWORK
       //;
       L   DBD 350;
       L   +0.5200000E+01;
       <R;
       S   M 182.7;
       //;
       L   DBD 350;
       L   +0.5200000E+01;
       >R;
       R   M 182.7;
       //;
       L   DBD 350;
       L   +0.6900000E+01;
       >R;
       S   M 182.6;
       //;
       L   DBD 350;
       L   +0.6900000E+01;
       <R;
       R   M 182.6;
  NETWORK
       //;
       L   DBD 374;
       L   +0.5200000E+01;
       <R;
       S   M 183.1;
       //;
       L   DBD 374;
       L   +0.5200000E+01;
       >R;
       R   M 183.1;
       //;
       L   DBD 374;
       L   +0.6900000E+01;
       >R;
       S   M 183.0;
       //;
       L   DBD 374;
       L   +0.6900000E+01;
       <R;
       R   M 183.0;
  NETWORK
       //;
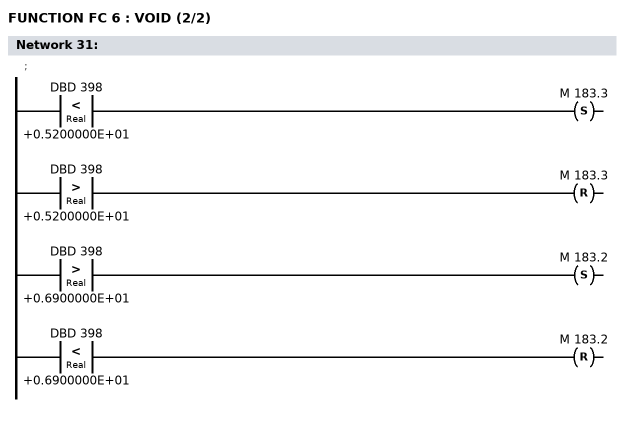
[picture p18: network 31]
       L   DBD 398;
       L   +0.5200000E+01;
       <R;
       S   M 183.3;
       //;
       L   DBD 398;
       L   +0.5200000E+01;
       >R;
       R   M 183.3;
       //;
       L   DBD 398;
       L   +0.6900000E+01;
       >R;
       S   M 183.2;
       //;
       L   DBD 398;
       L   +0.6900000E+01;
       <R;
       R   M 183.2;
  NETWORK
       OPN DB 152;
       L   DBD 48;
       L   +0.4000000E+03;
       >R;
       S   M 183.4;
       //;
       L   DBD 48;
       L   +0.3990000E+03;
       <R;
       R   M 183.4;
  NETWORK
       OPN DB 151;
       L   DBD 196;
       L   +0.1200000E+02;
       >R;
       S   M 184.0;
       //;
       L   DBD 196;
       L   +0.1150000E+02;
       <R;
       R   M 184.0;
  NETWORK
       //;
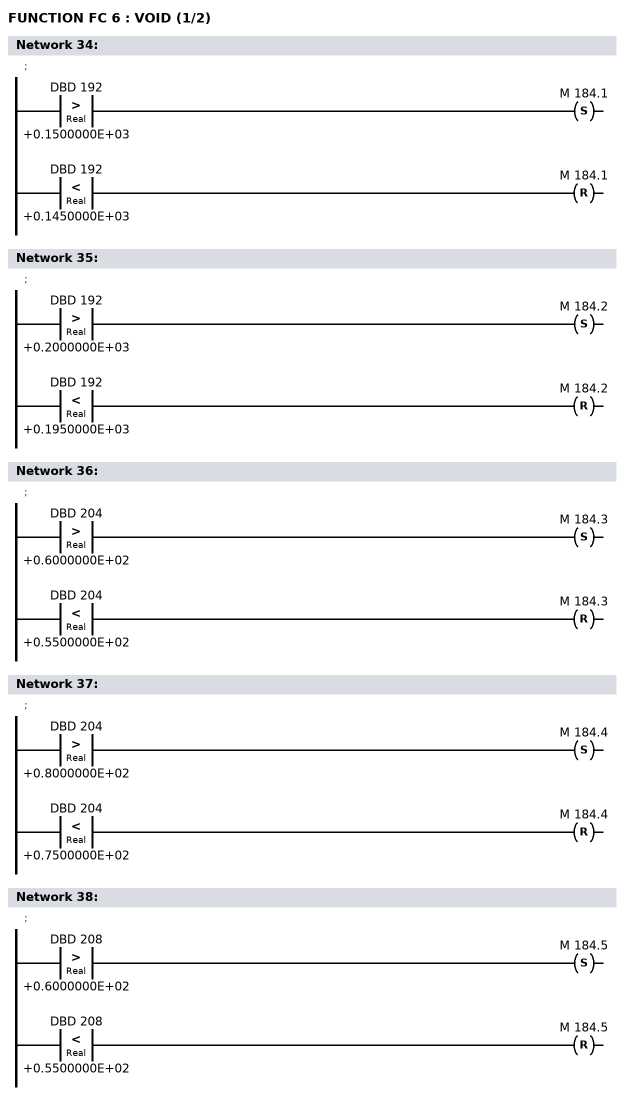
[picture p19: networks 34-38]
       L   DBD 192;
       L   +0.1500000E+03;
       >R;
       S   M 184.1;
       //;
       L   DBD 192;
       L   +0.1450000E+03;
       <R;
       R   M 184.1;
  NETWORK
       //;
       L   DBD 192;
       L   +0.2000000E+03;
       >R;
       S   M 184.2;
       //;
       L   DBD 192;
       L   +0.1950000E+03;
       <R;
       R   M 184.2;
  NETWORK
       //;
       L   DBD 204;
       L   +0.6000000E+02;
       >R;
       S   M 184.3;
       //;
       L   DBD 204;
       L   +0.5500000E+02;
       <R;
       R   M 184.3;
  NETWORK
       //;
       L   DBD 204;
       L   +0.8000000E+02;
       >R;
       S   M 184.4;
       //;
       L   DBD 204;
       L   +0.7500000E+02;
       <R;
       R   M 184.4;
  NETWORK
       //;
       L   DBD 208;
       L   +0.6000000E+02;
       >R;
       S   M 184.5;
       //;
       L   DBD 208;
       L   +0.5500000E+02;
       <R;
       R   M 184.5;
  NETWORK
       //;
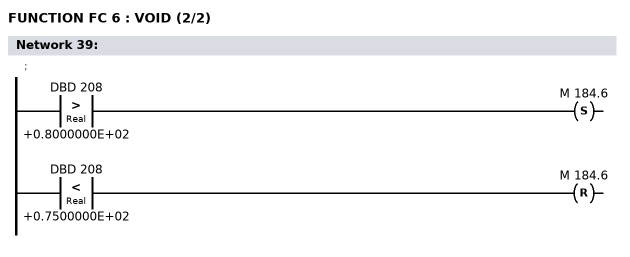
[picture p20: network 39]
       L   DBD 208;
       L   +0.8000000E+02;
       >R;
       S   M 184.6;
       //;
       L   DBD 208;
       L   +0.7500000E+02;
       <R;
       R   M 184.6;
  NETWORK
       OPN DB 94;
       A   M 184.2;
       L   DBW 14;
       SD  T 7;
  NETWORK


END_FUNCTION

FUNCTION FC 7 : VOID
  NAME: BIN_COMM  // BIN-COMM
  BEGIN
  NETWORK
       OPN DB 129;
       L   DBW 20;
       T   MW 100;
       L   DBW 22;
       T   MW 102;
       L   DBW 24;
       T   MW 108;
       L   DBB 27;
       T   MB 125;
       //;


END_FUNCTION

FUNCTION FC 9 : VOID
  NAME: RESET
  VAR_TEMP
   conv_akku1 :dword;
   conv_akku2 :dword;
   conv_stw   :word;
  END_VAR
  BEGIN
  NETWORK
       L   0;
       T   MW 200;
       //;
  M001:L   +0.0000000E+00;

       T   conv_akku1;
       TAK;
       T   conv_akku2;
       L   STW;
       T   conv_stw;
       L   MB 201;
       SLW 3;
       LAR1;
       L   conv_stw;
       T   STW;
       L   conv_akku2;
       L   conv_akku1;
       T  MD [ AR1, P#0.0 ];
       //;
       L   MW 200;
       +   4;
       T   MW 200;
       L   200;
       <I;
       JC  M001;
       //;
  NETWORK
       OPN DB 100;
       //;
       L   110;
       T   MW 200;
       //;
  M002:L   5;

       T   conv_akku1;
       TAK;
       T   conv_akku2;
       L   STW;
       T   conv_stw;
       L   MB 201;
       SLW 4;
       LAR1;
       L   conv_stw;
       T   STW;
       L   conv_akku2;
       L   conv_akku1;
       T  DBW [ AR1, P#0.0 ];
       //;
       L   MW 200;
       +   1;
       T   MW 200;
       L   200;
       <I;
       JC  M002;
       //;
  NETWORK
       OPN DB 110;
       //;
       L   110;
       T   MW 200;
       //;
  M003:L   20;

       T   conv_akku1;
       TAK;
       T   conv_akku2;
       L   STW;
       T   conv_stw;
       L   MB 201;
       SLW 4;
       LAR1;
       L   conv_stw;
       T   STW;
       L   conv_akku2;
       L   conv_akku1;
       T  DBW [ AR1, P#0.0 ];
       //;
       L   MW 200;
       +   1;
       T   MW 200;
       L   200;
       <I;
       JC  M003;
       //;
  NETWORK
  //      CALL FB 125;
  // *** Error in Line    1714  (FB  90):  Block does not exist. ***
       // (  $$IDENT :=  B#(0,0)
       // ,  $$IDENT :=  B#(0,255)
       // ,  $$IDENT :=  MB 240
       //  );
  NETWORK
       OPN DB 9;
       L   W#16#0;
       T   DBW 20;
       T   DBW 22;
       T   DBW 24;
       //;
       L   W#16#0;
       OPN DB 130;
       T   DBW 16;
       OPN DB 136;
       T   DBW 16;
  NETWORK


END_FUNCTION

FUNCTION FC 10 : VOID
  NAME: CP143
  BEGIN
  NETWORK
       O   M 0.0;
  //      CALL FB 126;
  // *** Error in Line    1742  (FB  91):  Block does not exist. ***
        // (  $$IDENT :=  B#(0,0)
        // ,  $$IDENT :=  B#(0,0)
        // ,  $$IDENT :=  MW 242
        // ,  $$IDENT :=  MB 244
       //  );
       O   M 0.0;
  //      CALL FB 127;
  // *** Error in Line    1750  (FB  91):  Block does not exist. ***
       // (  $$IDENT :=  B#(0,0)
       // ,  $$IDENT :=  B#(0,0)
       // ,  $$IDENT :=  MW 246
       // ,  $$IDENT :=  MB 248
       //  );
  NETWORK


END_FUNCTION

FUNCTION FC 11 : VOID
  NAME: SETAUTO  // SET AUTO
  VAR_TEMP
   conv_akku1 :dword;
   conv_akku2 :dword;
   conv_stw   :word;
  END_VAR
  BEGIN
  NETWORK
       AN  M 102.2;
       BEC;
  NETWORK
       OPN DB 100;
       L   10;
       T   DBW 2;
  M001:NOP 0;

       T   conv_akku1;
       L   STW;
       T   conv_stw;
       L   DBB 3;
       SLW 4;
       LAR1;
       L   conv_stw;
       T   STW;
       L   conv_akku1;
       L   DBW [ AR1, P#0.0 ];
       L   2#0000000100000000;
       OW;

       T   conv_akku1;
       TAK;
       T   conv_akku2;
       L   STW;
       T   conv_stw;
       L   DBB 3;
       SLW 4;
       LAR1;
       L   conv_stw;
       T   STW;
       L   conv_akku2;
       L   conv_akku1;
       T  DBW [ AR1, P#0.0 ];
       //;
       L   1;
       L   DBW 2;
       +I;
       T   DBW 2;
       L   99;
       <=I;
       JC  M001;
       //;
       OPN DB 110;
       L   10;
       T   DBW 2;
  M002:NOP 0;

       T   conv_akku1;
       L   STW;
       T   conv_stw;
       L   DBB 3;
       SLW 4;
       LAR1;
       L   conv_stw;
       T   STW;
       L   conv_akku1;
       L   DBW [ AR1, P#0.0 ];
       L   2#0000000100000000;
       OW;

       T   conv_akku1;
       TAK;
       T   conv_akku2;
       L   STW;
       T   conv_stw;
       L   DBB 3;
       SLW 4;
       LAR1;
       L   conv_stw;
       T   STW;
       L   conv_akku2;
       L   conv_akku1;
       T  DBW [ AR1, P#0.0 ];
       //;
       L   DBW 2;
       L   1;
       +I;
       T   DBW 2;
       L   69;
       <=I;
       JC  M002;
  NETWORK


END_FUNCTION

FUNCTION FC 12 : VOID
  NAME: CHKAUTO  // CHK AUTO
  VAR_TEMP
   conv_akku1 :dword;
   conv_stw   :word;
  END_VAR
  BEGIN
  NETWORK
  NETWORK
       OPN DB 100;
       L   10;
       T   DBW 2;
       A   M 0.0;
       =   M 105.6;
  M001:L   DBW 2;

       T   conv_akku1;
       L   STW;
       T   conv_stw;
       L   DBB 3;
       SLW 4;
       LAR1;
       L   conv_stw;
       T   STW;
       L   conv_akku1;
       L   DBW [ AR1, P#0.0 ];
       T   MW 206;
       A   M 206.0;
       A   M 105.6;
       =   M 105.6;
       //;
       L   1;
       L   DBW 2;
       +I;
       T   DBW 2;
       L   89;
       <=I;
       JC  M001;
       //;
       OPN DB 110;
       L   10;
       T   DBW 2;
  M002:L   DBW 2;

       T   conv_akku1;
       L   STW;
       T   conv_stw;
       L   DBB 3;
       SLW 4;
       LAR1;
       L   conv_stw;
       T   STW;
       L   conv_akku1;
       L   DBW [ AR1, P#0.0 ];
       T   MW 206;
       A   M 206.0;
       A   M 105.6;
       =   M 105.6;
       //;
       L   1;
       L   DBW 2;
       +I;
       T   DBW 2;
       L   57;
       <=I;
       JC  M002;
  NETWORK


END_FUNCTION

FUNCTION FC 13 : VOID
  NAME: INT_ACT  // INT.ACT
  VAR_TEMP
   conv_akku1 :dword;
   conv_akku2 :dword;
   conv_stw   :word;
  END_VAR
  BEGIN
  NETWORK
       AN  M 102.5;
       BEC;
  NETWORK
       OPN DB 100;
       L   10;
       T   DBW 2;
  M001:NOP 0;

       T   conv_akku1;
       L   STW;
       T   conv_stw;
       L   DBB 3;
       SLW 4;
       LAR1;
       L   conv_stw;
       T   STW;
       L   conv_akku1;
       L   DBW [ AR1, P#0.0 ];
       L   2#1111011111111111;
       AW;

       T   conv_akku1;
       TAK;
       T   conv_akku2;
       L   STW;
       T   conv_stw;
       L   DBB 3;
       SLW 4;
       LAR1;
       L   conv_stw;
       T   STW;
       L   conv_akku2;
       L   conv_akku1;
       T  DBW [ AR1, P#0.0 ];
       //;
       L   1;
       L   DBW 2;
       +I;
       T   DBW 2;
       L   99;
       <=I;
       JC  M001;
       //;
       OPN DB 110;
       L   10;
       T   DBW 2;
  M002:NOP 0;

       T   conv_akku1;
       L   STW;
       T   conv_stw;
       L   DBB 3;
       SLW 4;
       LAR1;
       L   conv_stw;
       T   STW;
       L   conv_akku1;
       L   DBW [ AR1, P#0.0 ];
       L   2#1111011111111111;
       AW;

       T   conv_akku1;
       TAK;
       T   conv_akku2;
       L   STW;
       T   conv_stw;
       L   DBB 3;
       SLW 4;
       LAR1;
       L   conv_stw;
       T   STW;
       L   conv_akku2;
       L   conv_akku1;
       T  DBW [ AR1, P#0.0 ];
       //;
       L   DBW 2;
       L   1;
       +I;
       T   DBW 2;
       L   69;
       <=I;
       JC  M002;
  NETWORK


END_FUNCTION

FUNCTION FC 14 : VOID
  NAME: CYCLIMET
  BEGIN
  NETWORK
       OPN DB 99;
       L   DBW 4;
       +   1;
       T   DBW 4;
       AN  M 4.2;
       BEC;
       //;
       L   DBW 28;
       T   DBW 30;
       L   DBW 26;
       T   DBW 28;
       L   DBW 24;
       T   DBW 26;
       L   DBW 22;
       T   DBW 24;
       L   DBW 20;
       T   DBW 22;
       L   DBW 18;
       T   DBW 20;
       L   DBW 16;
       T   DBW 18;
       L   DBW 14;
       T   DBW 16;
       L   DBW 12;
       T   DBW 14;
       //;
       L   DBW 4;
       L   DBW 10;
       <I;
       JC  M001;
       L   DBW 4;
       T   DBW 10;
       //;
  M001:L   DBW 4;
       L   DBW 8;
       >I;
       JC  M002;
       L   DBW 4;
       T   DBW 8;
       //;
  M002:L   DBW 4;
       T   DBW 12;
       L   0;
       T   DBW 4;
       //;
       L   DBW 12;
       L   DBW 14;
       +I;
       L   DBW 16;
       +I;
       L   DBW 18;
       +I;
       L   DBW 20;
       +I;
       L   DBW 22;
       +I;
       L   DBW 24;
       +I;
       L   DBW 26;
       +I;
       L   DBW 28;
       +I;
       L   DBW 30;
       +I;
       L   10;
       /I;
       L   W#16#FF;
       AW;
       T   DBW 6;
       //;
       L   1000;
       L   DBW 6;
       /I;
       L   W#16#FF;
       AW;
       T   DBW 34;
       //;
       L   1000;
       L   DBW 10;
       /I;
       L   W#16#3FF;
       AW;
       T   DBW 36;
       //;
       L   1000;
       L   DBW 8;
       /I;
       L   W#16#3FF;
       AW;
       T   DBW 38;


END_FUNCTION


FUNCTION FC 18 : VOID
  NAME: RST_CMD  // RST.CMD
  VAR_TEMP
   conv_akku1 :dword;
   conv_akku2 :dword;
   conv_stw   :word;
  END_VAR
  BEGIN
  NETWORK
       OPN DB 100;
       L   10;
       T   DBW 2;
  M001:L   DBW 2;

       T   conv_akku1;
       L   STW;
       T   conv_stw;
       L   DBB 3;
       SLW 4;
       LAR1;
       L   conv_stw;
       T   STW;
       L   conv_akku1;
       L   DBW [ AR1, P#0.0 ];
       L   2#1111100111111111;
       AW;

       T   conv_akku1;
       TAK;
       T   conv_akku2;
       L   STW;
       T   conv_stw;
       L   DBB 3;
       SLW 4;
       LAR1;
       L   conv_stw;
       T   STW;
       L   conv_akku2;
       L   conv_akku1;
       T  DBW [ AR1, P#0.0 ];
       //;
       L   1;
       L   DBW 2;
       +I;
       T   DBW 2;
       L   89;
       <=I;
       JC  M001;
  NETWORK
       OPN DB 110;
       L   10;
       T   DBW 2;
  M002:L   DBW 2;

       T   conv_akku1;
       L   STW;
       T   conv_stw;
       L   DBB 3;
       SLW 4;
       LAR1;
       L   conv_stw;
       T   STW;
       L   conv_akku1;
       L   DBW [ AR1, P#0.0 ];
       L   2#1111100111111111;
       AW;

       T   conv_akku1;
       TAK;
       T   conv_akku2;
       L   STW;
       T   conv_stw;
       L   DBB 3;
       SLW 4;
       LAR1;
       L   conv_stw;
       T   STW;
       L   conv_akku2;
       L   conv_akku1;
       T  DBW [ AR1, P#0.0 ];
       //;
       L   1;
       L   DBW 2;
       +I;
       T   DBW 2;
       L   57;
       <=I;
       JC  M002;
  NETWORK
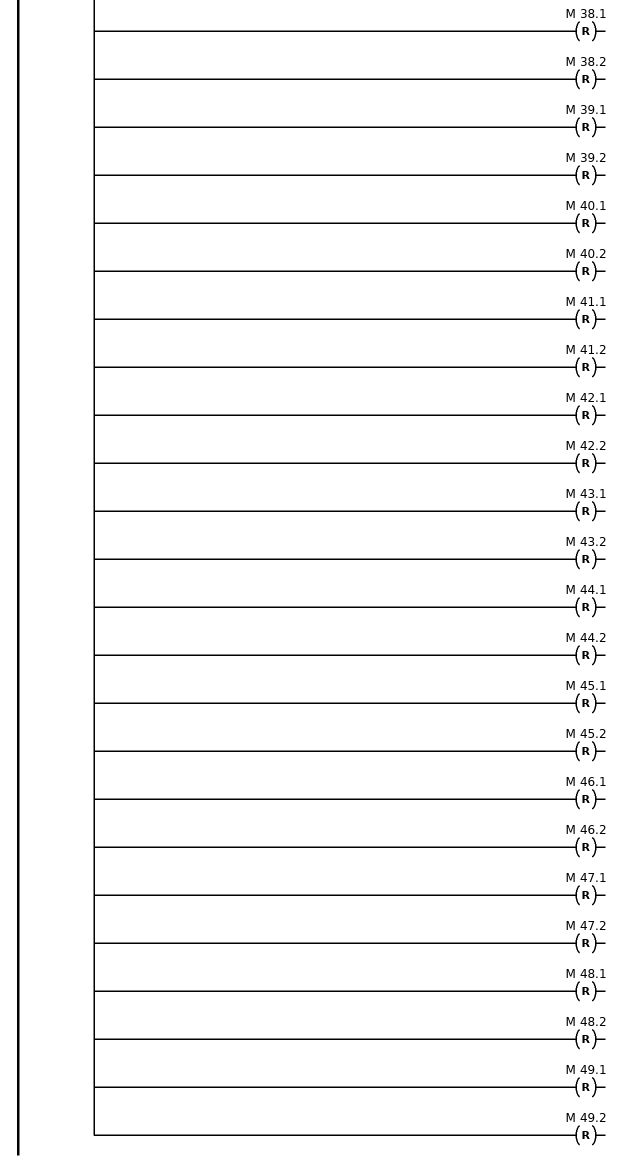
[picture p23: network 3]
       A   M 0.0;
       R   M 10.1;
       R   M 10.2;
       R   M 11.1;
       R   M 11.2;
       R   M 12.1;
       R   M 12.2;
       R   M 13.1;
       R   M 13.2;
       R   M 14.1;
       R   M 14.2;
       R   M 15.1;
       R   M 15.2;
       R   M 16.1;
       R   M 16.2;
       R   M 17.1;
       R   M 17.2;
       R   M 18.1;
       R   M 18.2;
       R   M 19.1;
       R   M 19.2;
       R   M 20.1;
       R   M 20.2;
       R   M 21.1;
       R   M 21.2;
       R   M 22.1;
       R   M 22.2;
       R   M 23.1;
       R   M 23.2;
       R   M 24.1;
       R   M 24.2;
       R   M 25.1;
       R   M 25.2;
       R   M 26.1;
       R   M 26.2;
       R   M 27.1;
       R   M 27.2;
       R   M 28.1;
       R   M 28.2;
       R   M 29.1;
       R   M 29.2;
       R   M 30.1;
       R   M 30.2;
       R   M 31.1;
       R   M 31.2;
       R   M 32.1;
       R   M 32.2;
       R   M 33.1;
       R   M 33.2;
       R   M 34.1;
       R   M 34.2;
       R   M 35.1;
       R   M 35.2;
       R   M 36.1;
       R   M 36.2;
       R   M 37.1;
       R   M 37.2;
       R   M 38.1;
       R   M 38.2;
       R   M 39.1;
       R   M 39.2;
       R   M 40.1;
       R   M 40.2;
       R   M 41.1;
       R   M 41.2;
       R   M 42.1;
       R   M 42.2;
       R   M 43.1;
       R   M 43.2;
       R   M 44.1;
       R   M 44.2;
       R   M 45.1;
       R   M 45.2;
       R   M 46.1;
       R   M 46.2;
       R   M 47.1;
       R   M 47.2;
       R   M 48.1;
       R   M 48.2;
       R   M 49.1;
       R   M 49.2;
  NETWORK
       A   M 0.0;
       R   M 50.1;
       R   M 50.2;
       R   M 51.1;
       R   M 51.2;
       R   M 52.1;
       R   M 52.2;
       R   M 53.1;
       R   M 53.2;
       R   M 54.1;
       R   M 54.2;
       R   M 55.1;
       R   M 55.2;
       R   M 56.1;
       R   M 56.2;
       R   M 57.1;
       R   M 57.2;
       R   M 58.1;
       R   M 58.2;
       R   M 59.1;
       R   M 59.2;
       R   M 60.1;
       R   M 60.2;
       R   M 61.1;
       R   M 61.2;
       R   M 62.1;
       R   M 62.2;
       R   M 63.1;
       R   M 63.2;
       R   M 64.1;
       R   M 64.2;
       R   M 65.1;
       R   M 65.2;
       R   M 66.1;
       R   M 66.2;
       R   M 67.1;
       R   M 67.2;
       R   M 68.1;
       R   M 68.2;
       R   M 69.1;
       R   M 69.2;
       R   M 70.1;
       R   M 70.2;
       R   M 71.1;
       R   M 71.2;
       R   M 72.1;
       R   M 72.2;
       R   M 73.1;
       R   M 73.2;
  NETWORK
       A   M 0.0;
       R   M 74.1;
       R   M 74.2;
       R   M 75.1;
       R   M 75.2;
       R   M 76.1;
       R   M 76.2;
       R   M 77.1;
       R   M 77.2;
       R   M 78.1;
       R   M 78.2;
       R   M 79.1;
       R   M 79.2;
       R   M 80.1;
       R   M 80.2;
       R   M 81.1;
       R   M 81.2;
       R   M 82.1;
       R   M 82.2;
       R   M 83.1;
       R   M 83.2;
       R   M 84.1;
       R   M 84.2;
       R   M 85.1;
       R   M 85.2;
       R   M 86.1;
       R   M 86.2;
       R   M 87.1;
       R   M 87.2;
       R   M 88.1;
       R   M 88.2;
       R   M 89.1;
       R   M 89.2;
  NETWORK
       A   M 0.0;
       R   M 110.1;
       R   M 110.2;
       R   M 111.1;
       R   M 111.2;
       R   M 112.1;
       R   M 112.2;
       R   M 113.1;
       R   M 113.2;
       R   M 114.1;
       R   M 114.2;
       R   M 115.1;
       R   M 115.2;
       R   M 116.1;
       R   M 116.2;
       R   M 117.1;
       R   M 117.2;
       R   M 118.1;
       R   M 118.2;
       R   M 119.1;
       R   M 119.2;
       R   M 120.1;
       R   M 120.2;
       R   M 121.1;
       R   M 121.2;
       R   M 122.1;
       R   M 122.2;
       R   M 123.1;
       R   M 123.2;
       R   M 124.1;
       R   M 124.2;
  NETWORK


END_FUNCTION

FUNCTION FC 19 : VOID
  NAME: BINSTATI
  BEGIN
  NETWORK
  TITLE = Status binair
  NETWORK
       OPN DB 120;
       L   IB 24;
       T   DBB 21;
       L   IB 25;
       T   DBB 20;
       L   IB 26;
       T   DBB 23;
       L   IB 27;
       T   DBB 22;
       L   IB 28;
       T   DBB 25;
       L   IB 29;
       T   DBB 24;
       L   IB 6;
       T   DBB 27;
       L   IB 7;
       T   DBB 26;
       L   IB 8;
       T   DBB 29;
       L   IB 9;
       T   DBB 28;
       L   IB 10;
       T   DBB 31;
       L   IB 11;
       T   DBB 30;
       //;
       L   IB 30;
       T   DBB 33;
       L   IB 31;
       T   DBB 32;
       L   IB 32;
       T   DBB 35;
       L   IB 33;
       T   DBB 34;
       //;
       L   IB 34;
       T   DBB 37;
       L   IB 35;
       T   DBB 36;
       //;
       A   I 2.2;
       =   DBX 23.0;
       A   I 2.3;
       =   DBX 23.1;
       A   I 2.4;
       =   DBX 23.2;
       A   I 7.4;
       =   DBX 23.3;
       //;
       A   M 0.0;
       =   DBX 36.0;            // in bedrijf melding vibro MK818.2
       A   I 2.6;               // Vooralarm vibro MK818.2
       =   DBX 36.1;
       A   I 2.7;               // Hoog-hoog alarm vibrp MK818.2
       =   DBX 36.2;
       //;
       A   I 4.2;
       =   DBX 25.0;
       A   I 4.3;
       =   DBX 25.1;
       A   I 4.6;
       =   DBX 25.2;
       A   I 5.0;
       =   DBX 25.3;
       A   I 5.1;
       =   DBX 25.4;
       A   I 1.2;
       =   DBX 25.5;
       A   I 1.3;
       =   DBX 25.6;
       A   I 1.4;
       =   DBX 25.7;
       //;
       L   MW 170;
       T   DBW 38;
       //;
       OPN DB 133;
       L   DBW 196;
       OPN DB 120;
       T   DBW 40;
       //;
       L   MW 104;
       T   DBW 42;
       //;
       L   MB 100;
       T   DBB 44;
       L   MB 176;
       T   DBB 45;
       //;
       L   MW 177;
       T   DBW 46;
       //;
       L   IW 36;
       T   DBW 48;
       //;
       L   MW 179;
       T   DBW 50;
       //;
       OPN DB 3;
       L   DBD 20;
       OPN DB 120;
       T   DBD 52;
       //;
       OPN DB 3;
       L   DBD 24;
       OPN DB 120;
       T   DBD 56;
       //;
       OPN DB 3;
       L   DBD 28;
       OPN DB 120;
       T   DBD 60;
  NETWORK
       A   I 0.0;
       =   M 200.0;
       A   I 0.2;
       =   M 200.1;
       A   I 0.6;
       =   M 200.2;
       A   I 3.4;
       =   M 200.3;
       A   I 3.5;
       =   M 200.4;
       A   I 3.6;
       =   M 200.5;
       A   I 12.2;
       =   M 200.6;
       A   I 12.3;
       =   M 200.7;
       A   I 12.4;
       =   M 201.0;
       A   I 12.5;
       =   M 201.1;
       A   I 12.6;
       =   M 201.2;
       A   I 13.1;
       =   M 201.3;
       A   I 13.2;
       =   M 201.4;
       A   I 13.3;
       =   M 201.5;
       A   I 14.1;
       =   M 201.6;
       A   I 14.2;
       =   M 201.7;
       //;
       L   MB 200;
       T   DBB 165;
       L   MB 201;
       T   DBB 164;
  NETWORK
       A   I 14.3;
       =   M 200.0;
       A   M 0.1;
       =   M 200.1;
       A   I 44.1;
       =   M 200.2;
       A   I 48.3;
       =   M 200.3;
       A   I 16.0;
       =   M 200.4;
       A   I 16.1;
       =   M 200.5;
       A   I 48.6;
       =   M 200.6;
       A   I 16.4;
       =   M 200.7;
       A   I 16.5;
       =   M 201.0;
       A   I 16.6;
       =   M 201.1;
       A   I 16.7;
       =   M 201.2;
       A   I 17.0;
       =   M 201.3;
       A   I 17.6;
       =   M 201.4;
       A   I 20.2;
       =   M 201.5;
       A   I 17.3;
       =   M 201.6;
       A   I 17.4;
       =   M 201.7;
       //;
       L   MB 200;
       T   DBB 167;
       L   MB 201;
       T   DBB 166;
  NETWORK
       A   I 16.2;
       =   DBX 24.4;
       A   I 16.3;
       =   DBX 24.5;
  NETWORK
       A   I 17.5;
       =   M 200.0;
       A   I 19.0;
       =   M 200.1;
       A   I 19.1;
       =   M 200.2;
       A   I 19.2;
       =   M 200.3;
       A   I 19.3;
       =   M 200.4;
       A   I 19.5;
       =   M 200.5;
       A   I 20.3;
       =   M 200.6;
       A   I 20.4;
       =   M 200.7;
       A   I 20.5;
       =   M 201.0;
       A   I 20.6;
       =   M 201.1;
       A   I 20.7;
       =   M 201.2;
       A   I 21.0;
       =   M 201.3;
       A   I 21.1;
       =   M 201.4;
       A   I 21.2;
       =   M 201.5;
       A   I 21.3;
       =   M 201.6;
       A   I 21.4;
       =   M 201.7;
       //;
       L   MB 200;
       T   DBB 169;
       L   MB 201;
       T   DBB 168;
  NETWORK
       A   I 21.5;
       =   M 200.0;
       A   I 18.7;
       =   M 200.1;
       A   I 37.4;
       =   M 200.2;
       A   I 37.5;
       =   M 200.3;
       A   I 37.6;
       =   M 200.4;
       A   I 37.7;
       =   M 200.5;
       A   I 38.0;
       =   M 200.6;
       A   I 38.1;
       =   M 200.7;
       A   I 38.2;
       =   M 201.0;
       A   I 5.7;
       =   M 201.1;
       A   I 38.4;
       =   M 201.2;
       A   I 38.5;
       =   M 201.3;
       A   I 38.6;
       =   M 201.4;
       A   I 38.7;
       =   M 201.5;
       A   I 39.0;
       =   M 201.6;
       A   I 39.1;
       =   M 201.7;
       //;
       L   MB 200;
       T   DBB 171;
       L   MB 201;
       T   DBB 170;
  NETWORK
       A   I 39.2;
       =   M 200.0;
       A   I 39.3;
       =   M 200.1;
       A   I 39.4;
       =   M 200.2;
       A   I 39.5;
       =   M 200.3;
       A   I 39.6;
       =   M 200.4;
       A   I 39.7;
       =   M 200.5;
       A   I 40.0;
       =   M 200.6;
       A   I 40.1;
       =   M 200.7;
       A   I 40.2;
       =   M 201.0;
       A   I 40.3;
       =   M 201.1;
       A   I 40.4;
       =   M 201.2;
       A   I 40.5;
       =   M 201.3;
       A   I 40.6;
       =   M 201.4;
       A   I 40.7;
       =   M 201.5;
       A   I 41.0;
       =   M 201.6;
       A   I 41.1;
       =   M 201.7;
       //;
       L   MB 200;
       T   DBB 173;
       L   MB 201;
       T   DBB 172;
  NETWORK
       A   I 41.2;
       =   M 200.0;
       A   I 41.3;
       =   M 200.1;
       A   I 41.4;
       =   M 200.2;
       A   I 41.5;
       =   M 200.3;
       A   I 41.6;
       =   M 200.4;
       A   I 41.7;
       =   M 200.5;
       A   I 43.0;
       =   M 200.6;
       A   I 43.1;
       =   M 200.7;
       A   I 43.2;
       =   M 201.0;
       A   I 43.6;
       =   M 201.1;
       A   I 47.2;
       =   M 201.2;
       A   I 11.5;
       =   M 201.3;
       A   I 23.1;
       =   M 201.4;
       A   I 44.7;
       =   M 201.5;
       A   I 42.3;
       =   M 201.6;
       A   I 23.4;
       =   M 201.7;
       //;
       L   MB 200;
       T   DBB 175;
       L   MB 201;
       T   DBB 174;
  NETWORK
       L   IB 46;
       T   DBB 177;
       L   IB 47;
       T   DBB 176;
       L   IB 48;
       T   DBB 179;
       L   IB 49;
       T   DBB 178;
       L   IB 50;
       T   DBB 181;
       L   IB 51;
       T   DBB 180;
  NETWORK
       A   I 18.0;
       =   M 201.0;
       A   I 18.1;
       =   M 201.1;
       A   I 18.2;
       =   M 201.2;
       A   I 18.3;
       =   M 201.3;
       A   I 18.6;
       =   M 201.4;
       A   I 20.0;
       =   M 201.5;
       A   I 20.1;
       =   M 201.6;
       A   I 22.5;
       =   M 201.7;
       A   I 19.7;
       =   M 200.0;
       A   I 18.5;
       =   M 200.1;
       A   I 21.6;
       =   M 200.2;
       A   I 21.7;
       =   M 200.3;
       A   I 18.4;
       =   M 200.4;
       A   I 19.4;
       =   M 200.5;
       A   I 19.6;
       =   M 200.6;
       A   I 4.7;
       =   M 200.7;
       //;
       L   MW 200;
       T   DBW 182;
       //;
  NETWORK
       A   I 13.4;
       =   M 201.0;
       A   I 44.4;
       =   M 201.1;
       A   I 44.3;
       =   M 201.2;
       A   I 22.3;
       =   M 201.3;
       A   I 22.2;
       =   M 201.4;
       A   I 22.0;
       =   M 201.5;
       A   I 22.4;
       =   M 201.6;
       A   I 22.5;
       =   M 201.7;
       A   I 22.6;
       =   M 200.0;
       A   I 22.7;
       =   M 200.1;
       A   I 23.0;
       =   M 200.2;
       A   I 45.4;
       =   M 200.3;
       A   I 45.5;
       =   M 200.4;
       A   I 41.7;
       =   M 200.5;
       A   I 43.0;
       =   M 200.6;
       A   I 43.1;
       =   M 200.7;
       //;
       L   MW 200;
       T   DBW 184;
  NETWORK
       A   I 22.1;
       =   M 201.0;
       //;
       L   MW 200;
       T   DBW 186;
  NETWORK
       //;
       //;
       A   I 18.1;
       =   M 201.0;
       A   I 32.6;
       =   M 201.1;
       A   I 33.0;
       =   M 201.4;
       AN  M 181.2;
       =   M 201.5;
       A   T 61;
       =   M 201.6;
       A   T 62;
       =   M 201.7;
       AN  M 178.6;
       =   M 200.0;
       AN  I 24.1;
       =   M 200.1;
       O   I 37.0;
       O   I 15.0;
       =   M 200.2;
       A   I 5.6;
       =   M 200.3;
       A   I 4.7;
       =   M 200.4;
       AN  I 32.5;
       =   M 200.5;
       AN  M 60.5;
       =   M 200.7;
       //;
       L   MW 200;
       T   DBW 188;
       //;
  NETWORK
       //;
       OPN DB 133;
       L   DBB 197;
       OPN DB 120;
       T   DBB 197;
       //;
       A   M 174.2;
       =   DBX 196.1;
       A   M 174.3;
       =   DBX 196.2;
       A   M 174.4;
       =   DBX 196.3;
       A   M 174.5;
       =   DBX 196.4;
       A   M 174.6;
       =   DBX 196.5;
       //;


END_FUNCTION

FUNCTION FC 20 : VOID
  NAME: RESET_BC  // RESET-BC
  BEGIN
  NETWORK
       OPN DB 129;
       L   W#16#3;
       L   MW 102;
       AW;
       T   DBW 22;
       L   W#16#0;
       T   DBW 20;
       T   DBB 27;
       //;


END_FUNCTION

FUNCTION FC 21 : VOID
  NAME: ANALIN  // ANAL IN
  VAR_TEMP
   conv_akku1 :dword;
   conv_akku2 :dword;
   conv_stw   :word;
  END_VAR
  BEGIN
  NETWORK
  NETWORK
       OPN DB 130;
  M005:L   DBW 16;
       +   2;
       L   126;
       AW;
       T   DBW 16;
       T   MW 216;
       +   128;
       T   MW 218;
       L   DBW 16;
       SRW 1;
       +   10;
       T   MW 220;
       +   64;
       T   MW 222;
       +   64;
       T   MW 224;
       //;

       T   conv_akku1;
       L   STW;
       T   conv_stw;
       L   MB 219;
       SLW 3;
       LAR1;
       L   conv_stw;
       T   STW;
       L   conv_akku1;
       L   PIW [ AR1, P#0.0 ];
       L   8;
       /I;
       L   0;
       <I;
       JC  M001;
       TAK;
  M001:NOP 0;

       T   conv_akku1;
       TAK;
       T   conv_akku2;
       L   STW;
       T   conv_stw;
       L   MB 221;
       SLW 4;
       LAR1;
       L   conv_stw;
       T   STW;
       L   conv_akku2;
       L   conv_akku1;
       T  DBW [ AR1, P#0.0 ];
       T   MW 234;
       //;

       T   conv_akku1;
       L   STW;
       T   conv_stw;
       L   MB 217;
       SLW 3;
       LAR1;
       L   conv_stw;
       T   STW;
       L   conv_akku1;
       L   PIW [ AR1, P#0.0 ];
       L   8;
       /I;
       +   -512;
       L   0;
       <I;
       JC  M002;
       TAK;
  M002:NOP 0;

       T   conv_akku1;
       TAK;
       T   conv_akku2;
       L   STW;
       T   conv_stw;
       L   MB 223;
       SLW 4;
       LAR1;
       L   conv_stw;
       T   STW;
       L   conv_akku2;
       L   conv_akku1;
       T  DBW [ AR1, P#0.0 ];
       T   MW 236;
       //;

       T   conv_akku1;
       L   STW;
       T   conv_stw;
       L   MB 219;
       SLW 3;
       LAR1;
       L   conv_stw;
       T   STW;
       L   conv_akku1;
       L   PIW [ AR1, P#0.0 ];
       L   8;
       /I;
       +   39;
       L   0;
       <I;
       JC  M003;
       TAK;
  M003:NOP 0;

       T   conv_akku1;
       TAK;
       T   conv_akku2;
       L   STW;
       T   conv_stw;
       L   MB 225;
       SLW 4;
       LAR1;
       L   conv_stw;
       T   STW;
       L   conv_akku2;
       L   conv_akku1;
       T  DBW [ AR1, P#0.0 ];
       T   MW 238;
       //;
       JU  M004;
  M007:JU  M005;
  M004:OPN DB 131;

       T   conv_akku1;
       L   STW;
       T   conv_stw;
       L   MB 221;
       SLW 4;
       LAR1;
       L   conv_stw;
       T   STW;
       L   conv_akku1;
       L   DBB [ AR1, P#0.0 ];
       SLW 3;
       L   MW 234;
       <I;
       =   M 200.7;
       =   M 240.7;

       T   conv_akku1;
       L   STW;
       T   conv_stw;
       L   MB 221;
       SLW   4;
       +     8;
       LAR1;
       L   conv_stw;
       T   STW;
       L   conv_akku1;
       L   DBB [ AR1, P#0.0 ];
       SLW 3;
       L   MW 234;
       >I;
       =   M 200.4;
       =   M 240.4;
       A   M 240.7;
       O   M 240.4;
       =   M 240.6;

       T   conv_akku1;
       L   STW;
       T   conv_stw;
       L   MB 223;
       SLW 4;
       LAR1;
       L   conv_stw;
       T   STW;
       L   conv_akku1;
       L   DBB [ AR1, P#0.0 ];
       SLW 3;
       L   MW 236;
       <I;
       =   M 204.7;
       =   M 244.7;

       T   conv_akku1;
       L   STW;
       T   conv_stw;
       L   MB 223;
       SLW   4;
       +     8;
       LAR1;
       L   conv_stw;
       T   STW;
       L   conv_akku1;
       L   DBB [ AR1, P#0.0 ];
       SLW 3;
       L   MW 236;
       >I;
       =   M 204.4;
       =   M 244.4;
       A   M 244.7;
       O   M 244.4;
       =   M 244.6;

       T   conv_akku1;
       L   STW;
       T   conv_stw;
       L   MB 225;
       SLW 4;
       LAR1;
       L   conv_stw;
       T   STW;
       L   conv_akku1;
       L   DBB [ AR1, P#0.0 ];
       SLW 3;
       L   MW 238;
       <I;
       =   M 208.7;
       =   M 248.7;

       T   conv_akku1;
       L   STW;
       T   conv_stw;
       L   MB 225;
       SLW   4;
       +     8;
       LAR1;
       L   conv_stw;
       T   STW;
       L   conv_akku1;
       L   DBB [ AR1, P#0.0 ];
       SLW 3;
       L   MW 238;
       >I;
       =   M 208.4;
       =   M 248.4;
       A   M 248.7;
       O   M 248.4;
       =   M 248.6;
       OPN DB 134;

       T   conv_akku1;
       L   STW;
       T   conv_stw;
       L   MB 221;
       SLW 4;
       LAR1;
       L   conv_stw;
       T   STW;
       L   conv_akku1;
       L   DBB [ AR1, P#0.0 ];
       SLW 3;
       OPN DB 133;

       T   conv_akku1;
       L   STW;
       T   conv_stw;
       L   MB 221;
       SLW 4;
       LAR1;
       L   conv_stw;
       T   STW;
       L   conv_akku1;
       L   DBW [ AR1, P#0.0 ];
       <I;
       =   M 212.7;
       =   M 252.7;
       OPN DB 134;

       T   conv_akku1;
       L   STW;
       T   conv_stw;
       L   MB 221;
       SLW   4;
       +     8;
       LAR1;
       L   conv_stw;
       T   STW;
       L   conv_akku1;
       L   DBB [ AR1, P#0.0 ];
       SLW 3;
       OPN DB 133;

       T   conv_akku1;
       L   STW;
       T   conv_stw;
       L   MB 221;
       SLW 4;
       LAR1;
       L   conv_stw;
       T   STW;
       L   conv_akku1;
       L   DBW [ AR1, P#0.0 ];
       >I;
       =   M 212.4;
       =   M 252.4;
       A   M 252.7;
       O   M 252.4;
       =   M 252.6;
       JU  M006;
  M009:JU  M007;
  M006:OPN DB 132;

       T   conv_akku1;
       L   STW;
       T   conv_stw;
       L   MB 221;
       SLW 4;
       LAR1;
       L   conv_stw;
       T   STW;
       L   conv_akku1;
       L   DBB [ AR1, P#0.0 ];
       SLW 3;
       L   MW 234;
       <I;
       =   M 200.6;

       T   conv_akku1;
       L   STW;
       T   conv_stw;
       L   MB 221;
       SLW   4;
       +     8;
       LAR1;
       L   conv_stw;
       T   STW;
       L   conv_akku1;
       L   DBB [ AR1, P#0.0 ];
       SLW 3;
       L   MW 234;
       >I;
       =   M 200.5;
       AN  M 240.6;
       A(;
       O   M 200.6;
       O   M 200.5;
       );
       =   M 240.5;

       T   conv_akku1;
       L   STW;
       T   conv_stw;
       L   MB 223;
       SLW 4;
       LAR1;
       L   conv_stw;
       T   STW;
       L   conv_akku1;
       L   DBB [ AR1, P#0.0 ];
       SLW 3;
       L   MW 236;
       <I;
       =   M 204.6;

       T   conv_akku1;
       L   STW;
       T   conv_stw;
       L   MB 223;
       SLW   4;
       +     8;
       LAR1;
       L   conv_stw;
       T   STW;
       L   conv_akku1;
       L   DBB [ AR1, P#0.0 ];
       SLW 3;
       L   MW 236;
       >I;
       =   M 204.5;
       AN  M 244.6;
       A(;
       O   M 204.6;
       O   M 204.5;
       );
       =   M 244.5;

       T   conv_akku1;
       L   STW;
       T   conv_stw;
       L   MB 225;
       SLW 4;
       LAR1;
       L   conv_stw;
       T   STW;
       L   conv_akku1;
       L   DBB [ AR1, P#0.0 ];
       SLW 3;
       L   MW 238;
       <I;
       =   M 208.6;

       T   conv_akku1;
       L   STW;
       T   conv_stw;
       L   MB 225;
       SLW   4;
       +     8;
       LAR1;
       L   conv_stw;
       T   STW;
       L   conv_akku1;
       L   DBB [ AR1, P#0.0 ];
       SLW 3;
       L   MW 238;
       >I;
       =   M 208.5;
       AN  M 248.6;
       A(;
       O   M 208.6;
       O   M 208.5;
       );
       =   M 248.5;
       OPN DB 135;

       T   conv_akku1;
       L   STW;
       T   conv_stw;
       L   MB 221;
       SLW 4;
       LAR1;
       L   conv_stw;
       T   STW;
       L   conv_akku1;
       L   DBB [ AR1, P#0.0 ];
       SLW 3;
       OPN DB 133;

       T   conv_akku1;
       L   STW;
       T   conv_stw;
       L   MB 221;
       SLW 4;
       LAR1;
       L   conv_stw;
       T   STW;
       L   conv_akku1;
       L   DBW [ AR1, P#0.0 ];
       <I;
       =   M 212.6;
       OPN DB 135;

       T   conv_akku1;
       L   STW;
       T   conv_stw;
       L   MB 221;
       SLW   4;
       +     8;
       LAR1;
       L   conv_stw;
       T   STW;
       L   conv_akku1;
       L   DBB [ AR1, P#0.0 ];
       SLW 3;
       OPN DB 133;

       T   conv_akku1;
       L   STW;
       T   conv_stw;
       L   MB 221;
       SLW 4;
       LAR1;
       L   conv_stw;
       T   STW;
       L   conv_akku1;
       L   DBW [ AR1, P#0.0 ];
       >I;
       =   M 212.5;
       AN  M 252.6;
       A(;
       O   M 212.6;
       O   M 212.5;
       );
       =   M 252.5;
       //;
       OPN DB 130;
       L   DBW 16;
       L   2#0000000000001110;
       AW;
       L   14;
       ==I;
       JC  M008;
       L   MD 200;
       RRD 4;
       T   MD 200;
       L   MD 204;
       RRD 4;
       T   MD 204;
       L   MD 208;
       RRD 4;
       T   MD 208;
       L   MD 212;
       RRD 4;
       T   MD 212;
       L   MD 240;
       RRD 4;
       T   MD 240;
       L   MD 244;
       RRD 4;
       T   MD 244;
       L   MD 248;
       RRD 4;
       T   MD 248;
       L   MD 252;
       RRD 4;
       T   MD 252;
       JU  M009;
  M008:  NOP 0;
    NETWORK
       L   DBW 16;
       SRW 4;
       SLW 1;
       +   10;
       T   MW 226;
       +   16;
       T   MW 228;
       +   16;
       T   MW 230;
       +   16;
       T   MW 232;
       //;
       OPN DB 136;
       L   MD 200;
       RRD 16;

       T   conv_akku1;
       TAK;
       T   conv_akku2;
       L   STW;
       T   conv_stw;
       L   MB 227;
       SLW 4;
       LAR1;
       L   conv_stw;
       T   STW;
       L   conv_akku2;
       L   conv_akku1;
       T  DBD [ AR1, P#0.0 ];
       L   MD 204;
       RRD 16;

       T   conv_akku1;
       TAK;
       T   conv_akku2;
       L   STW;
       T   conv_stw;
       L   MB 229;
       SLW 4;
       LAR1;
       L   conv_stw;
       T   STW;
       L   conv_akku2;
       L   conv_akku1;
       T  DBD [ AR1, P#0.0 ];
       L   MD 208;
       RRD 16;

       T   conv_akku1;
       TAK;
       T   conv_akku2;
       L   STW;
       T   conv_stw;
       L   MB 231;
       SLW 4;
       LAR1;
       L   conv_stw;
       T   STW;
       L   conv_akku2;
       L   conv_akku1;
       T  DBD [ AR1, P#0.0 ];
       L   MD 212;
       RRD 16;

       T   conv_akku1;
       TAK;
       T   conv_akku2;
       L   STW;
       T   conv_stw;
       L   MB 233;
       SLW 4;
       LAR1;
       L   conv_stw;
       T   STW;
       L   conv_akku2;
       L   conv_akku1;
       T  DBD [ AR1, P#0.0 ];
       //;
  NETWORK


END_FUNCTION

FUNCTION FC 22 : VOID
  NAME: PID_IN  // PID-IN
  BEGIN
  NETWORK
       //;
       OPN DB 133;
       L   DBW 76;
       SLW 3;
       OPN DB 201;
       T   DBW 338;
  NETWORK
       OPN DB 133;
       L   DBW 32;
       L   DBW 34;
       +I;
       SLW 3;
       OPN DB 202;
       T   DBW 338;
  NETWORK
       OPN DB 203;
       A   M 0.0;
       =   DBX 360.6;
  NETWORK
       OPN DB 130;
       L   DBW 320;
       SLW 3;
       OPN DB 204;
       T   DBW 338;
  NETWORK
       OPN DB 130;
       L   DBW 322;
       SLW 3;
       OPN DB 205;
       T   DBW 338;
  NETWORK
       OPN DB 133;
       L   DBW 26;
       L   DBW 28;
       +I;
       SLW 3;
       OPN DB 210;
       T   DBW 338;
  NETWORK


END_FUNCTION

FUNCTION FC 23 : VOID
  NAME: PID_OUT  // PID-OUT
  BEGIN
  NETWORK
  NETWORK
       OPN DB 138;
       L   DBW 22;
       DTR;
       L   +0.2048000E+04;
       /R;
       //;
       OPN DB 201;
       L   DBW 416;
       T   PQW 140;
       T   PQW 142;
       DTR;
       *R;
       RND;
       T   PQW 144;
       T   PQW 146;
  NETWORK
       OPN DB 210;
       L   DBW 416;
       T   PQW 134;
       T   PQW 136;
  NETWORK


END_FUNCTION

FUNCTION FC 24 : VOID
  NAME: BEREKEN1
  BEGIN
  NETWORK
  NETWORK
       OPN DB 133;
       //;
       L   PIW 138;
       L   8;
       /I;
       +   39;
       T   DBW 172;
       L   PIW 140;
       L   8;
       /I;
       +   39;
       T   DBW 174;
       L   PIW 142;
       L   8;
       /I;
       +   39;
       T   DBW 176;
       //;
       L   PIW 144;
       L   8;
       /I;
       +   39;
       T   DBW 178;
       L   PIW 146;
       L   8;
       /I;
       +   39;
       T   DBW 180;
       L   PIW 148;
       L   8;
       /I;
       +   39;
       T   DBW 182;
       //;
       L   PIW 150;
       L   8;
       /I;
       +   39;
       T   DBW 184;
       L   PIW 152;
       L   8;
       /I;
       +   39;
       T   DBW 186;
       L   PIW 154;
       L   8;
       /I;
       +   39;
       T   DBW 188;
  NETWORK
       L   83;
       T   DBW 198;
       //;
       //;
       //;
       L   DBW 172;
       L   DBW 174;
       -I;
       L   0;
       TAK;
       <I;
       JC  M001;
       INVI;
  M001:L   DBW 198;
       >I;
       =   DBX 191.0;
       //;
       L   DBW 174;
       L   DBW 176;
       -I;
       L   0;
       TAK;
       <I;
       JC  M002;
       INVI;
  M002:L   DBW 198;
       >I;
       =   DBX 191.1;
       //;
       L   DBW 172;
       L   DBW 176;
       -I;
       L   0;
       TAK;
       <I;
       JC  M003;
       INVI;
  M003:L   DBW 198;
       >I;
       =   DBX 191.2;
       //;
       //;
       L   DBW 178;
       L   DBW 180;
       -I;
       L   0;
       TAK;
       <I;
       JC  M004;
       INVI;
  M004:L   DBW 198;
       >I;
       =   DBX 193.0;
       //;
       L   DBW 180;
       L   DBW 182;
       -I;
       L   0;
       TAK;
       <I;
       JC  M005;
       INVI;
  M005:L   DBW 198;
       >I;
       =   DBX 193.1;
       //;
       L   DBW 178;
       L   DBW 182;
       -I;
       L   0;
       TAK;
       <I;
       JC  M006;
       INVI;
  M006:L   DBW 198;
       >I;
       =   DBX 193.2;
       //;
       L   DBW 184;
       L   DBW 186;
       -I;
       L   0;
       TAK;
       <I;
       JC  M007;
       INVI;
  M007:L   DBW 198;
       >I;
       =   DBX 195.0;
       //;
       L   DBW 186;
       L   DBW 188;
       -I;
       L   0;
       TAK;
       <I;
       JC  M008;
       INVI;
  M008:L   DBW 198;
       >I;
       =   DBX 195.1;
       //;
       L   DBW 184;
       L   DBW 188;
       -I;
       L   0;
       TAK;
       <I;
       JC  M009;
       INVI;
  M009:L   DBW 198;
       >I;
       =   DBX 195.2;
  NETWORK
       L   DBW 190;
       L   5;
       ==I;
       AN  DBX 197.1;
       AN  DBX 197.2;
       S   DBX 197.0;
       L   DBW 190;
       L   3;
       ==I;
       AN  DBX 197.0;
       AN  DBX 197.2;
       S   DBX 197.1;
       L   DBW 190;
       L   6;
       ==I;
       AN  DBX 197.0;
       AN  DBX 197.1;
       S   DBX 197.2;
       L   DBW 190;
       L   0;
       <>I;
       AN  M 2.0;
       JC  M010;
       A   M 0.0;
       R   DBX 197.0;
       R   DBX 197.1;
       R   DBX 197.2;
  M010:NOP 0;
       L   DBW 192;
       L   5;
       ==I;
       AN  DBX 197.4;
       AN  DBX 197.5;
       S   DBX 197.3;
       L   DBW 192;
       L   3;
       ==I;
       AN  DBX 197.3;
       AN  DBX 197.5;
       S   DBX 197.4;
       L   DBW 192;
       L   6;
       ==I;
       AN  DBX 197.3;
       AN  DBX 197.4;
       S   DBX 197.5;
       L   DBW 192;
       L   0;
       <>I;
       AN  M 2.0;
       JC  M011;
       A   M 0.0;
       R   DBX 197.3;
       R   DBX 197.4;
       R   DBX 197.5;
  M011:NOP 0;
       L   DBW 194;
       L   5;
       ==I;
       AN  DBX 197.7;
       AN  DBX 196.0;
       S   DBX 197.6;
       L   DBW 194;
       L   3;
       ==I;
       AN  DBX 197.6;
       AN  DBX 196.0;
       S   DBX 197.7;
       L   DBW 194;
       L   6;
       ==I;
       AN  DBX 197.6;
       AN  DBX 197.7;
       S   DBX 196.0;
       L   DBW 194;
       L   0;
       <>I;
       AN  M 2.0;
       JC  M012;
       A   M 0.0;
       R   DBX 197.6;
       R   DBX 197.7;
       R   DBX 196.0;
  M012:NOP 0;
  NETWORK
       A   DBX 197.0;
       JC  M013;
       A   DBX 197.1;
       JC  M014;
       A   DBX 197.2;
       JC  M015;
       L   DBW 172;
       L   DBW 174;
       +I;
       L   DBW 176;
       +I;
       L   3;
       /I;
       T   DBW 56;
       JU  M016;
  M013:L   DBW 174;
       L   DBW 176;
       +I;
       SRW 1;
       T   DBW 56;
       JU  M016;
  M014:L   DBW 172;
       L   DBW 176;
       +I;
       SRW 1;
       T   DBW 56;
       JU  M016;
  M015:L   DBW 172;
       L   DBW 174;
       +I;
       SRW 1;
       T   DBW 56;
       //;
  M016:A   DBX 197.3;
       JC  M017;
       A   DBX 197.4;
       JC  M018;
       A   DBX 197.5;
       JC  M019;
       L   DBW 178;
       L   DBW 180;
       +I;
       L   DBW 182;
       +I;
       L   3;
       /I;
       T   DBW 58;
       JU  M020;
  M017:L   DBW 180;
       L   DBW 182;
       +I;
       SRW 1;
       T   DBW 58;
       JU  M020;
  M018:L   DBW 178;
       L   DBW 182;
       +I;
       SRW 1;
       T   DBW 58;
       JU  M020;
  M019:L   DBW 178;
       L   DBW 180;
       +I;
       SRW 1;
       T   DBW 58;
       //;
  M020:A   DBX 197.6;
       JC  M021;
       A   DBX 197.7;
       JC  M022;
       A   DBX 196.0;
       JC  M023;
       L   DBW 184;
       L   DBW 186;
       +I;
       L   DBW 188;
       +I;
       L   3;
       /I;
       T   DBW 60;
       JU  M024;
  M021:L   DBW 186;
       L   DBW 188;
       +I;
       SRW 1;
       T   DBW 60;
       JU  M024;
  M022:L   DBW 184;
       L   DBW 188;
       +I;
       SRW 1;
       T   DBW 60;
       JU  M024;
  M023:L   DBW 184;
       L   DBW 186;
       +I;
       SRW 1;
       T   DBW 60;
  M024:  NOP 0;
    NETWORK
       OPN DB 133;
       L   DBW 56;
       L   DBW 58;
       +I;
       SRW 1;
       T   DBW 76;
  NETWORK


END_FUNCTION

FUNCTION FC 25 : VOID
  NAME: BEREKEN2
  BEGIN
  NETWORK
  NETWORK
       OPN DB 130;
       L   DBW 68;
       +   104;
       DTR;
       L   +0.9765625E-02;
       *R;
       T   MD 200;
       //;
       L   MD 200;
       L   MD 200;
       *R;
       T   MD 204;
       L   -0.3333333E+00;
       L   MD 204;
       /R;
       T   MD 204;
       L   +0.2000000E+01;
       L   MD 200;
       /R;
       L   MD 204;
       +R;
       T   MD 210;
  NETWORK
       OPN DB 130;
       L   DBW 276;
       DTR;
       L   +0.6025389E+00;
       *R;
       T   MD 200;
       //;
       L   MD 200;
       L   MD 200;
       *R;
       L   +0.3500000E-08;
       *R;
       T   MD 204;
       L   MD 200;
       L   +0.9000000E-07;
       *R;
       L   MD 204;
       +R;
       L   +0.9999999E-03;
       +R;
       T   MD 214;
  NETWORK
       OPN DB 130;
       L   DBW 16;
       L   14;
       <>I;
       JC  M001;
       //;
       L   DBW 36;
       DTR;
       L   +0.4882813E+01;
       *R;
       L   MD 210;
       *R;
       L   +0.1317000E+00;
       /R;
       L   +0.2048000E+00;
       *R;
       RND;
       L   4096;
       >I;
       JC  M002;
       TAK;
  M002:OPN DB 133;
       T   DBW 20;
  M001:  NOP 0;
    NETWORK
       OPN DB 130;
       L   DBW 16;
       L   30;
       <>I;
       JC  M003;
       //;
       L   DBW 38;
       DTR;
       L   +0.4882813E+01;
       *R;
       L   MD 210;
       *R;
       L   +0.1317000E+00;
       /R;
       L   +0.2048000E+00;
       *R;
       RND;
       L   4096;
       >I;
       JC  M004;
       TAK;
  M004:OPN DB 133;
       T   DBW 22;
  M003:  NOP 0;
    NETWORK
       OPN DB 133;
       L   DBW 20;
       L   DBW 22;
       -I;
       L   0;
       <I;
       JC  M005;
       TAK;
  M005:T   DBW 24;
  NETWORK
       OPN DB 130;
       L   DBW 16;
       L   46;
       <>I;
       JC  M006;
       //;
       L   DBW 40;
       DTR;
       L   +0.1220703E+02;
       *R;
       L   MD 214;
       *R;
       L   +0.1155000E-02;
       /R;
       L   +0.8192000E-01;
       *R;
       RND;
       L   4096;
       >I;
       JC  M007;
       TAK;
  M007:OPN DB 133;
       T   DBW 26;
  M006:  NOP 0;
    NETWORK
       OPN DB 130;
       L   DBW 16;
       L   62;
       <>I;
       JC  M008;
       //;
       L   DBW 42;
       DTR;
       L   +0.1220703E+02;
       *R;
       L   MD 214;
       *R;
       L   +0.1155000E-02;
       /R;
       L   +0.8192000E-01;
       *R;
       RND;
       L   4096;
       >I;
       JC  M009;
       TAK;
  M009:OPN DB 133;
       T   DBW 28;
  M008:  NOP 0;
    NETWORK
       OPN DB 130;
       L   DBW 16;
       L   78;
       <>I;
       JC  M010;
       //;
       OPN DB 130;
       L   DBW 44;
       OPN DB 133;
       T   DBW 30;
  M010:  NOP 0;
    NETWORK
       OPN DB 130;
       L   DBW 16;
       L   30;
       <>I;
       JC  M011;
       //;
       OPN DB 133;
       L   DBW 208;
       T   DBW 210;
       L   DBW 206;
       T   DBW 208;
       L   DBW 204;
       T   DBW 206;
       L   DBW 202;
       T   DBW 204;
       //;
       OPN DB 130;
       L   DBW 78;
       OPN DB 133;
       T   DBW 202;
       //;
       L   DBW 202;
       L   DBW 204;
       +I;
       L   DBW 206;
       +I;
       L   DBW 208;
       +I;
       L   DBW 210;
       +I;
       L   5;
       /I;
       T   DBW 82;
  M011:  NOP 0;
    NETWORK
       OPN DB 133;
       L   DBW 26;
       L   DBW 28;
       +I;
       L   4096;
       >I;
       JC  M012;
       TAK;
  M012:T   DBW 84;
  NETWORK


END_FUNCTION


FUNCTION FC 32 : VOID
  NAME: BER_MEET  // BER.MEET
  BEGIN
  NETWORK
       OPN DB 151;
       L   DBD 80;
       L   DBD 84;
       +R;
       OPN DB 150;
       T   DBD 256;
  NETWORK
       //;
       OPN DB 152;
       L   DBD 20;
       L   DBD 24;
       +R;
       L   DBD 28;
       +R;
       L   DBD 32;
       +R;
       L   DBD 36;
       +R;
       L   DBD 40;
       +R;
       L   +0.6000000E+01;
       /R;
       OPN DB 150;
       T   DBD 264;
  NETWORK
       //;
       OPN DB 133;
       L   DBW 26;
       L   DBW 28;
       +I;
  //      CALL OB 220;
  // *** Error in Line    4851  (FB 151):  Block does not exist. ***
       DTR;
       L   +0.4096000E+04;
       /R;
       L   +0.5000000E+05;
       *R;
       OPN DB 150;
       T   DBD 268;
  NETWORK
       OPN DB 133;
       L   DBW 26;
  //      CALL OB 220;
  // *** Error in Line    4863  (FB 151):  Block does not exist. ***
       DTR;
       L   +0.2048000E+04;
       /R;
       L   +0.2500000E+05;
       *R;
       OPN DB 150;
       T   DBD 40;
  NETWORK
       OPN DB 133;
       L   DBW 28;
  //      CALL OB 220;
  // *** Error in Line    4875  (FB 151):  Block does not exist. ***
       DTR;
       L   +0.2048000E+04;
       /R;
       L   +0.2500000E+05;
       *R;
       OPN DB 150;
       T   DBD 44;
  NETWORK
       OPN DB 150;
       //;
       L   DBD 28;
       L   DBD 92;
       +R;
       L   +0.2000000E+01;
       /R;
       T   DBD 272;
       //;
       L   DBD 344;
       L   +0.9000000E+00;
       *R;
       T   DBD 320;
       //;
       L   DBD 272;
       L   +0.9999999E-01;
       *R;
       T   DBD 332;
       L   DBD 320;
       +R;
       T   DBD 344;
       //;
       L   2#0000000011111110;
       L   DBB 346;
       AW;
       T   DBB 346;
       //;
  NETWORK
       //;
       L   DBD 144;
       L   DBD 248;
       +R;
       L   +0.2000000E+01;
       /R;
       T   DBD 276;
       //;
       L   DBD 348;
       L   +0.9000000E+00;
       *R;
       T   DBD 324;
       //;
       L   DBD 276;
       L   +0.9999999E-01;
       *R;
       T   DBD 336;
       L   DBD 324;
       +R;
       T   DBD 348;
       //;
       L   2#0000000011111110;
       L   DBB 350;
       AW;
       T   DBB 350;
       //;
  NETWORK
       //;
       L   DBD 252;
       L   DBD 136;
       +R;
       L   +0.2000000E+01;
       /R;
       T   DBD 280;
       //;
       L   DBD 352;
       L   +0.9000000E+00;
       *R;
       T   DBD 328;
       //;
       L   DBD 280;
       L   +0.9999999E-01;
       *R;
       T   DBD 340;
       L   DBD 328;
       +R;
       T   DBD 352;
       //;
       L   2#0000000011111110;
       L   DBB 354;
       AW;
       T   DBB 354;
       //;
  NETWORK
       //;
       //;
       L   DBD 204;
       //;
       L   DBD 368;
       L   +0.9500000E+00;
       *R;
       T   DBD 360;
       //;
       L   DBD 204;
       L   +0.5000000E-01;
       *R;
       T   DBD 364;
       L   DBD 360;
       +R;
       T   DBD 368;
       //;
  NETWORK
       L   DBD 140;
       L   DBD 192;
       +R;
       L   +0.2000000E+01;
       /R;
       T   DBD 284;
  NETWORK
       //;
       L   DBD 196;
       L   DBD 200;
       +R;
       L   +0.2000000E+01;
       /R;
       T   DBD 288;
  NETWORK
       //;
       L   DBD 244;
       L   +0.2850000E+01;
       *R;
       T   DBD 292;
  NETWORK
       //;
       OPN DB 133;
       L   DBW 20;
  //      CALL OB 220;
  // *** Error in Line    5009  (FB 151):  Block does not exist. ***
       DTR;
       L   +0.2048000E+04;
       /R;
       L   +0.1000000E+05;
       *R;
       OPN DB 150;
       T   DBD 296;
  NETWORK
       OPN DB 181;
       L   DBD 210;
       RND;
       ITB;
       OPN DB 138;
       T   DBW 58;
  NETWORK
       OPN DB 181;
       L   DBD 214;
       RND;
       ITB;
       OPN DB 138;
       T   DBW 60;
  NETWORK
       OPN DB 150;
       //;
       L   +0.0000000E+00;
       AN  M 180.3;
       JC  M001;
       L   +0.1000000E+03;
  M001:T   DBD 300;
       //;
  NETWORK


END_FUNCTION


FUNCTION FC 34 : VOID
  NAME: REGELAAR
  VAR_INPUT
    DBRE      :block_db;  // DBRE
    DBSC      :block_db;  // DBSC
    P         :dword;     // P
    TI        :dword;     // TI
    TD        :dword;     // TD
    SOLL      :dword;     // SOLL
    HAND      :word;      // HAND
    H_A       :word;      // H/A
    DBIS      :block_db;  // DBIS
    IST       :dword;     // IST
    _TIME     :real;      // TIME
    VAN       :real;      // VAN
    TOT       :real;      // TOT
    VRYG      :bool;      // VRYG
    BIPO      :bool;      // BIPO
  END_VAR
  VAR_OUTPUT
    UIT       :dword;     // UIT
  END_VAR
  BEGIN
  NETWORK
       OPN #DBIS ;
       L   #TOT;
       L   #VAN;
       -R;
       T   MD 150;
       L   #IST;
       L   #VAN;
       -R;
       L   MD 150;
       /R;
       OPN #DBRE ;
       T   DBD 44;
       //;
       OPN #DBSC ;
       L   #TOT;
       L   #VAN;
       -R;
       T   MD 154;
       L   #SOLL;
       L   #VAN;
       -R;
       L   MD 154;
       /R;
       OPN #DBRE ;
       T   DBD 18;
       //;
       //;
       //;
       OPN #DBSC ;
       //;
       L   #P;
       OPN #DBRE ;
       T   DBD 2;
       //;
       OPN #DBSC ;
       L   #_TIME;
       L   #TI;
       /R;
       OPN #DBRE ;
       T   DBD 10;
       //;
       OPN #DBSC ;
       L   #TD;
       L   #_TIME;
       /R;
       OPN #DBRE ;
       T   DBD 14;
       //;
       OPN #DBSC ;
       L   #HAND;
  //      CALL OB 220;
  // *** Error in Line    5222  (FB 201):  Block does not exist. ***
       DTR;
       L   +0.1000000E+03;
       /R;
       OPN #DBRE ;
       T   DBD 24;
       //;
       OPN #DBSC ;
       L   #H_A;
       T   MW 150;
       OPN #DBRE ;
       A   M 151.0;
       =   DBX 23.0;
       //;
       A   #VRYG;
       JC  M001;
       //;
       L   +0.1000000E+01;
       T   DBD 6;
       T   DBD 28;
       //;
       L   +0.0000000E+00;
       T   DBD 32;
       //;
       L   2#0000000111100001;
       T   DBW 22;
       //;
       AN  #BIPO;
       JC  M001;
       //;
       L   -0.1000000E+01;
       T   DBD 32;
       //;
  M001:AN  #VRYG;
       =   DBX 23.2;
       //;
  //      CALL OB 251;
  // *** Error in Line    5259  (FB 201):  Block does not exist. ***
       //;
       L   DBD 92;
       OPN #DBSC ;
       L   +0.1000000E+03;
       *R;
       T   #UIT;


END_FUNCTION

FUNCTION FC 36 : VOID
  NAME: TAKT
  BEGIN
  NETWORK
       L   MB 160;
       SLW 1;
       A   M 160.4;
       T   MB 160;
       S   M 160.0;
       //;
       L   MB 161;
       SLW 1;
       A   M 161.7;
       T   MB 161;
       S   M 161.0;
       //;
       L   MD 162;
       SLD 1;
       A   M 162.7;
       T   MD 162;
       S   M 165.0;


END_FUNCTION

FUNCTION FC 37 : VOID
  NAME: PID_VRIJ  // PID-VRIJ
  BEGIN
  NETWORK
       OPN DB 94;
       //;
       A(;
       A   I 13.6;
       L   DBW 138;
       SP  T 69;
       NOP 0;
       NOP 0;
       NOP 0;
       A   T 69;
       );
       =   M 106.5;
       //;
       A(;
       O   I 13.7;
       O   I 14.6;
       L   DBW 140;
       SP  T 70;
       NOP 0;
       NOP 0;
       NOP 0;
       A   T 70;
       );
       =   M 106.6;
       //;
  NETWORK
       A   M 0.0;
       L   DBW 132;
       SP  T 66;
       NOP 0;
       NOP 0;
       NOP 0;
       A   T 66;
       =   M 106.2;
       //;
       AN  M 106.2;
       JC  M001;
       OPN DB 180;
       L   10;
       T   DBW 454;
       A   M 106.2;
       R   DBX 457.0;
  M001:NOP 0;
  NETWORK
       OPN DB 94;
       A   M 0.0;
       L   DBW 134;
       SP  T 67;
       NOP 0;
       NOP 0;
       NOP 0;
       A   T 67;
       =   M 106.3;
       //;
       AN  M 106.3;
       JC  M002;
       OPN DB 180;
       L   10;
       T   DBW 478;
       A   M 106.3;
       R   DBX 481.0;
  M002:NOP 0;
  NETWORK
       OPN DB 94;
       A   I 28.1;
       L   DBW 146;
       SD  T 73;
       NOP 0;
       NOP 0;
       NOP 0;
       A   T 73;
       =   M 105.2;
       //;
       A   M 105.2;
       L   DBW 136;
       SP  T 68;
       NOP 0;
       NOP 0;
       NOP 0;
       A   T 68;
       =   M 106.4;
       //;
       AN  M 106.4;
       JC  M003;
       OPN DB 180;
       L   10;
       T   DBW 502;
       A   M 106.4;
       R   DBX 505.0;
  M003:NOP 0;
  NETWORK
       OPN DB 152;
       L   DBD 44;
       L   +0.6000000E+03;
       >R;
       S   M 105.3;
       L   DBD 44;
       L   +0.5500000E+03;
       <R;
       R   M 105.3;
       //;
       OPN DB 100;
       A   DBX 94.3;
       S   M 105.3;
       //;
  NETWORK
       AN  M 175.6;
       AN  M 175.7;
       AN  T 60;
       AN  M 182.0;
       =   M 105.4;
       JC  M004;
       //;
       OPN DB 180;
       A   M 105.7;
       JC  M005;
       L   DBW 22;
       T   DBW 0;
       S   M 105.7;
       //;
  M005:L   10;
       T   DBW 22;
       R   DBX 25.0;
       JU  M006;
       //;
  M004:AN  M 105.7;
       JC  M006;
       OPN DB 180;
       L   DBW 0;
       T   DBW 22;
       R   M 105.7;
       //;
  M006:  NOP 0;
    NETWORK
       //;
       //;
       OPN DB 180;
       L   DBD 302;
       L   +0.4044000E+01;
       *R;
       L   +0.2052940E+02;
       -R;
       T   DBD 290;
       //;
       AN  M 182.3;
       JC  M007;
       L   +0.5000000E+00;
       T   DBD 290;
  M007:NOP 0;
       AN  M 182.2;
       JC  M008;
       L   +0.7375000E+01;
       T   DBD 290;
       //;
  M008:  NOP 0;
    NETWORK
       L   DBD 326;
       OPN DB 180;
       L   +0.4044000E+01;
       *R;
       L   +0.2052940E+02;
       -R;
       T   DBD 314;
       //;
       AN  M 182.5;
       JC  M009;
       L   +0.5000000E+00;
       T   DBD 314;
  M009:NOP 0;
       AN  M 182.4;
       JC  M010;
       L   +0.7375000E+01;
       T   DBD 314;
       //;
  M010:  NOP 0;
    NETWORK
       L   DBD 350;
       OPN DB 180;
       L   +0.4044000E+01;
       *R;
       L   +0.2052940E+02;
       -R;
       T   DBD 338;
       //;
       AN  M 182.7;
       JC  M011;
       L   +0.5000000E+00;
       T   DBD 338;
       //;
  M011:AN  M 182.6;
       JC  M012;
       L   +0.7375000E+01;
       T   DBD 338;
       //;
  M012:  NOP 0;
    NETWORK
       L   DBD 374;
       OPN DB 180;
       L   +0.4044000E+01;
       *R;
       L   +0.2052940E+02;
       -R;
       T   DBD 362;
       //;
       AN  M 183.1;
       JC  M013;
       L   +0.5000000E+00;
       T   DBD 362;
       //;
  M013:AN  M 183.0;
       JC  M014;
       L   +0.7375000E+01;
       T   DBD 362;
       //;
  M014:  NOP 0;
    NETWORK
       L   DBD 398;
       OPN DB 180;
       L   +0.4044000E+01;
       *R;
       L   +0.2052940E+02;
       -R;
       T   DBD 386;
       //;
       AN  M 183.3;
       JC  M015;
       L   +0.5000000E+00;
       T   DBD 386;
       //;
  M015:AN  M 183.2;
       JC  M016;
       L   +0.7375000E+01;
       T   DBD 386;
       //;
  M016:  NOP 0;
    NETWORK
       A   M 108.4;
       =   M 186.2;
       //;


END_FUNCTION

